VERSION 5.8 ;
BUSBITCHARS "[]" ;
DIVIDERCHAR "/" ;
UNITS
    DATABASE MICRONS 1000 ;
END UNITS

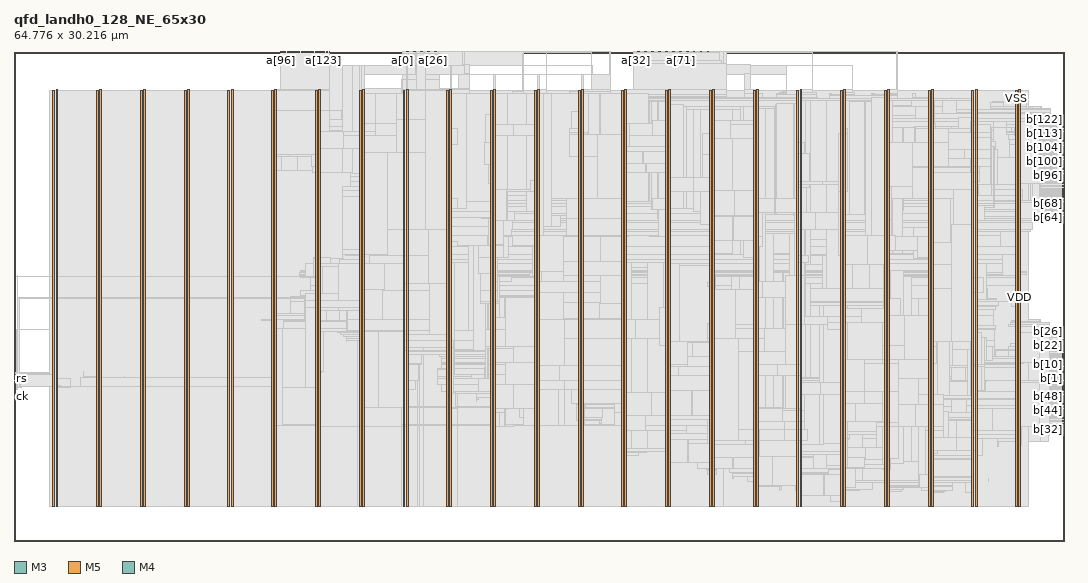
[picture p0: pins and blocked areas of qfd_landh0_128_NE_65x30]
MACRO qfd_landh0_128_NE_65x30
  FOREIGN qfd_landh0_128_NE_65x30 0 0 ;
  CLASS BLOCK ;
  SIZE 64.776 BY 30.216 ;
  PIN a[0]
    DIRECTION INPUT ;
    USE SIGNAL ;
    PORT
      LAYER M3 ;
        RECT  23.94 30.179 23.958 30.216 ;
    END
  END a[0]
  PIN a[100]
    DIRECTION INPUT ;
    USE SIGNAL ;
    PORT
      LAYER M5 ;
        RECT  16.848 30.132 16.872 30.216 ;
    END
  END a[100]
  PIN a[101]
    DIRECTION INPUT ;
    USE SIGNAL ;
    PORT
      LAYER M5 ;
        RECT  16.944 30.132 16.968 30.216 ;
    END
  END a[101]
  PIN a[102]
    DIRECTION INPUT ;
    USE SIGNAL ;
    PORT
      LAYER M5 ;
        RECT  17.04 30.132 17.064 30.216 ;
    END
  END a[102]
  PIN a[103]
    DIRECTION INPUT ;
    USE SIGNAL ;
    PORT
      LAYER M5 ;
        RECT  17.136 30.132 17.16 30.216 ;
    END
  END a[103]
  PIN a[104]
    DIRECTION INPUT ;
    USE SIGNAL ;
    PORT
      LAYER M5 ;
        RECT  17.232 30.132 17.256 30.216 ;
    END
  END a[104]
  PIN a[105]
    DIRECTION INPUT ;
    USE SIGNAL ;
    PORT
      LAYER M5 ;
        RECT  17.328 30.132 17.352 30.216 ;
    END
  END a[105]
  PIN a[106]
    DIRECTION INPUT ;
    USE SIGNAL ;
    PORT
      LAYER M5 ;
        RECT  17.424 30.132 17.448 30.216 ;
    END
  END a[106]
  PIN a[107]
    DIRECTION INPUT ;
    USE SIGNAL ;
    PORT
      LAYER M5 ;
        RECT  17.52 30.132 17.544 30.216 ;
    END
  END a[107]
  PIN a[108]
    DIRECTION INPUT ;
    USE SIGNAL ;
    PORT
      LAYER M5 ;
        RECT  17.616 30.132 17.64 30.216 ;
    END
  END a[108]
  PIN a[109]
    DIRECTION INPUT ;
    USE SIGNAL ;
    PORT
      LAYER M5 ;
        RECT  17.712 30.132 17.736 30.216 ;
    END
  END a[109]
  PIN a[10]
    DIRECTION INPUT ;
    USE SIGNAL ;
    PORT
      LAYER M3 ;
        RECT  24.66 30.179 24.678 30.216 ;
    END
  END a[10]
  PIN a[110]
    DIRECTION INPUT ;
    USE SIGNAL ;
    PORT
      LAYER M5 ;
        RECT  17.808 30.132 17.832 30.216 ;
    END
  END a[110]
  PIN a[111]
    DIRECTION INPUT ;
    USE SIGNAL ;
    PORT
      LAYER M5 ;
        RECT  17.904 30.132 17.928 30.216 ;
    END
  END a[111]
  PIN a[112]
    DIRECTION INPUT ;
    USE SIGNAL ;
    PORT
      LAYER M5 ;
        RECT  18 30.132 18.024 30.216 ;
    END
  END a[112]
  PIN a[113]
    DIRECTION INPUT ;
    USE SIGNAL ;
    PORT
      LAYER M5 ;
        RECT  18.096 30.132 18.12 30.216 ;
    END
  END a[113]
  PIN a[114]
    DIRECTION INPUT ;
    USE SIGNAL ;
    PORT
      LAYER M5 ;
        RECT  18.192 30.132 18.216 30.216 ;
    END
  END a[114]
  PIN a[115]
    DIRECTION INPUT ;
    USE SIGNAL ;
    PORT
      LAYER M5 ;
        RECT  18.288 30.132 18.312 30.216 ;
    END
  END a[115]
  PIN a[116]
    DIRECTION INPUT ;
    USE SIGNAL ;
    PORT
      LAYER M5 ;
        RECT  18.384 30.132 18.408 30.216 ;
    END
  END a[116]
  PIN a[117]
    DIRECTION INPUT ;
    USE SIGNAL ;
    PORT
      LAYER M5 ;
        RECT  18.48 30.132 18.504 30.216 ;
    END
  END a[117]
  PIN a[118]
    DIRECTION INPUT ;
    USE SIGNAL ;
    PORT
      LAYER M5 ;
        RECT  18.576 30.132 18.6 30.216 ;
    END
  END a[118]
  PIN a[119]
    DIRECTION INPUT ;
    USE SIGNAL ;
    PORT
      LAYER M5 ;
        RECT  18.672 30.132 18.696 30.216 ;
    END
  END a[119]
  PIN a[11]
    DIRECTION INPUT ;
    USE SIGNAL ;
    PORT
      LAYER M3 ;
        RECT  24.732 30.179 24.75 30.216 ;
    END
  END a[11]
  PIN a[120]
    DIRECTION INPUT ;
    USE SIGNAL ;
    PORT
      LAYER M5 ;
        RECT  18.768 30.132 18.792 30.216 ;
    END
  END a[120]
  PIN a[121]
    DIRECTION INPUT ;
    USE SIGNAL ;
    PORT
      LAYER M5 ;
        RECT  18.864 30.132 18.888 30.216 ;
    END
  END a[121]
  PIN a[122]
    DIRECTION INPUT ;
    USE SIGNAL ;
    PORT
      LAYER M5 ;
        RECT  18.96 30.132 18.984 30.216 ;
    END
  END a[122]
  PIN a[123]
    DIRECTION INPUT ;
    USE SIGNAL ;
    PORT
      LAYER M5 ;
        RECT  19.056 30.132 19.08 30.216 ;
    END
  END a[123]
  PIN a[124]
    DIRECTION INPUT ;
    USE SIGNAL ;
    PORT
      LAYER M5 ;
        RECT  19.152 30.132 19.176 30.216 ;
    END
  END a[124]
  PIN a[125]
    DIRECTION INPUT ;
    USE SIGNAL ;
    PORT
      LAYER M5 ;
        RECT  19.248 30.132 19.272 30.216 ;
    END
  END a[125]
  PIN a[126]
    DIRECTION INPUT ;
    USE SIGNAL ;
    PORT
      LAYER M5 ;
        RECT  19.344 30.132 19.368 30.216 ;
    END
  END a[126]
  PIN a[127]
    DIRECTION INPUT ;
    USE SIGNAL ;
    PORT
      LAYER M5 ;
        RECT  19.44 30.132 19.464 30.216 ;
    END
  END a[127]
  PIN a[12]
    DIRECTION INPUT ;
    USE SIGNAL ;
    PORT
      LAYER M3 ;
        RECT  24.804 30.179 24.822 30.216 ;
    END
  END a[12]
  PIN a[13]
    DIRECTION INPUT ;
    USE SIGNAL ;
    PORT
      LAYER M3 ;
        RECT  24.876 30.179 24.894 30.216 ;
    END
  END a[13]
  PIN a[14]
    DIRECTION INPUT ;
    USE SIGNAL ;
    PORT
      LAYER M3 ;
        RECT  24.948 30.179 24.966 30.216 ;
    END
  END a[14]
  PIN a[15]
    DIRECTION INPUT ;
    USE SIGNAL ;
    PORT
      LAYER M3 ;
        RECT  25.02 30.179 25.038 30.216 ;
    END
  END a[15]
  PIN a[16]
    DIRECTION INPUT ;
    USE SIGNAL ;
    PORT
      LAYER M3 ;
        RECT  25.092 30.179 25.11 30.216 ;
    END
  END a[16]
  PIN a[17]
    DIRECTION INPUT ;
    USE SIGNAL ;
    PORT
      LAYER M3 ;
        RECT  25.164 30.179 25.182 30.216 ;
    END
  END a[17]
  PIN a[18]
    DIRECTION INPUT ;
    USE SIGNAL ;
    PORT
      LAYER M3 ;
        RECT  25.236 30.179 25.254 30.216 ;
    END
  END a[18]
  PIN a[19]
    DIRECTION INPUT ;
    USE SIGNAL ;
    PORT
      LAYER M3 ;
        RECT  25.308 30.179 25.326 30.216 ;
    END
  END a[19]
  PIN a[1]
    DIRECTION INPUT ;
    USE SIGNAL ;
    PORT
      LAYER M3 ;
        RECT  24.012 30.179 24.03 30.216 ;
    END
  END a[1]
  PIN a[20]
    DIRECTION INPUT ;
    USE SIGNAL ;
    PORT
      LAYER M3 ;
        RECT  25.38 30.179 25.398 30.216 ;
    END
  END a[20]
  PIN a[21]
    DIRECTION INPUT ;
    USE SIGNAL ;
    PORT
      LAYER M3 ;
        RECT  25.452 30.179 25.47 30.216 ;
    END
  END a[21]
  PIN a[22]
    DIRECTION INPUT ;
    USE SIGNAL ;
    PORT
      LAYER M3 ;
        RECT  25.524 30.179 25.542 30.216 ;
    END
  END a[22]
  PIN a[23]
    DIRECTION INPUT ;
    USE SIGNAL ;
    PORT
      LAYER M3 ;
        RECT  25.596 30.179 25.614 30.216 ;
    END
  END a[23]
  PIN a[24]
    DIRECTION INPUT ;
    USE SIGNAL ;
    PORT
      LAYER M3 ;
        RECT  25.668 30.179 25.686 30.216 ;
    END
  END a[24]
  PIN a[25]
    DIRECTION INPUT ;
    USE SIGNAL ;
    PORT
      LAYER M3 ;
        RECT  25.74 30.179 25.758 30.216 ;
    END
  END a[25]
  PIN a[26]
    DIRECTION INPUT ;
    USE SIGNAL ;
    PORT
      LAYER M3 ;
        RECT  25.812 30.179 25.83 30.216 ;
    END
  END a[26]
  PIN a[27]
    DIRECTION INPUT ;
    USE SIGNAL ;
    PORT
      LAYER M3 ;
        RECT  25.884 30.179 25.902 30.216 ;
    END
  END a[27]
  PIN a[28]
    DIRECTION INPUT ;
    USE SIGNAL ;
    PORT
      LAYER M3 ;
        RECT  25.956 30.179 25.974 30.216 ;
    END
  END a[28]
  PIN a[29]
    DIRECTION INPUT ;
    USE SIGNAL ;
    PORT
      LAYER M3 ;
        RECT  26.028 30.179 26.046 30.216 ;
    END
  END a[29]
  PIN a[2]
    DIRECTION INPUT ;
    USE SIGNAL ;
    PORT
      LAYER M3 ;
        RECT  24.084 30.179 24.102 30.216 ;
    END
  END a[2]
  PIN a[30]
    DIRECTION INPUT ;
    USE SIGNAL ;
    PORT
      LAYER M3 ;
        RECT  26.1 30.179 26.118 30.216 ;
    END
  END a[30]
  PIN a[31]
    DIRECTION INPUT ;
    USE SIGNAL ;
    PORT
      LAYER M3 ;
        RECT  26.172 30.179 26.19 30.216 ;
    END
  END a[31]
  PIN a[32]
    DIRECTION INPUT ;
    USE SIGNAL ;
    PORT
      LAYER M3 ;
        RECT  38.34 30.179 38.358 30.216 ;
    END
  END a[32]
  PIN a[33]
    DIRECTION INPUT ;
    USE SIGNAL ;
    PORT
      LAYER M3 ;
        RECT  38.412 30.179 38.43 30.216 ;
    END
  END a[33]
  PIN a[34]
    DIRECTION INPUT ;
    USE SIGNAL ;
    PORT
      LAYER M3 ;
        RECT  38.484 30.179 38.502 30.216 ;
    END
  END a[34]
  PIN a[35]
    DIRECTION INPUT ;
    USE SIGNAL ;
    PORT
      LAYER M3 ;
        RECT  38.556 30.179 38.574 30.216 ;
    END
  END a[35]
  PIN a[36]
    DIRECTION INPUT ;
    USE SIGNAL ;
    PORT
      LAYER M3 ;
        RECT  38.628 30.179 38.646 30.216 ;
    END
  END a[36]
  PIN a[37]
    DIRECTION INPUT ;
    USE SIGNAL ;
    PORT
      LAYER M3 ;
        RECT  38.7 30.179 38.718 30.216 ;
    END
  END a[37]
  PIN a[38]
    DIRECTION INPUT ;
    USE SIGNAL ;
    PORT
      LAYER M3 ;
        RECT  38.772 30.179 38.79 30.216 ;
    END
  END a[38]
  PIN a[39]
    DIRECTION INPUT ;
    USE SIGNAL ;
    PORT
      LAYER M3 ;
        RECT  38.844 30.179 38.862 30.216 ;
    END
  END a[39]
  PIN a[3]
    DIRECTION INPUT ;
    USE SIGNAL ;
    PORT
      LAYER M3 ;
        RECT  24.156 30.179 24.174 30.216 ;
    END
  END a[3]
  PIN a[40]
    DIRECTION INPUT ;
    USE SIGNAL ;
    PORT
      LAYER M3 ;
        RECT  38.916 30.179 38.934 30.216 ;
    END
  END a[40]
  PIN a[41]
    DIRECTION INPUT ;
    USE SIGNAL ;
    PORT
      LAYER M3 ;
        RECT  38.988 30.179 39.006 30.216 ;
    END
  END a[41]
  PIN a[42]
    DIRECTION INPUT ;
    USE SIGNAL ;
    PORT
      LAYER M3 ;
        RECT  39.06 30.179 39.078 30.216 ;
    END
  END a[42]
  PIN a[43]
    DIRECTION INPUT ;
    USE SIGNAL ;
    PORT
      LAYER M3 ;
        RECT  39.132 30.179 39.15 30.216 ;
    END
  END a[43]
  PIN a[44]
    DIRECTION INPUT ;
    USE SIGNAL ;
    PORT
      LAYER M3 ;
        RECT  39.204 30.179 39.222 30.216 ;
    END
  END a[44]
  PIN a[45]
    DIRECTION INPUT ;
    USE SIGNAL ;
    PORT
      LAYER M3 ;
        RECT  39.276 30.179 39.294 30.216 ;
    END
  END a[45]
  PIN a[46]
    DIRECTION INPUT ;
    USE SIGNAL ;
    PORT
      LAYER M3 ;
        RECT  39.348 30.179 39.366 30.216 ;
    END
  END a[46]
  PIN a[47]
    DIRECTION INPUT ;
    USE SIGNAL ;
    PORT
      LAYER M3 ;
        RECT  39.42 30.179 39.438 30.216 ;
    END
  END a[47]
  PIN a[48]
    DIRECTION INPUT ;
    USE SIGNAL ;
    PORT
      LAYER M3 ;
        RECT  39.492 30.179 39.51 30.216 ;
    END
  END a[48]
  PIN a[49]
    DIRECTION INPUT ;
    USE SIGNAL ;
    PORT
      LAYER M3 ;
        RECT  39.564 30.179 39.582 30.216 ;
    END
  END a[49]
  PIN a[4]
    DIRECTION INPUT ;
    USE SIGNAL ;
    PORT
      LAYER M3 ;
        RECT  24.228 30.179 24.246 30.216 ;
    END
  END a[4]
  PIN a[50]
    DIRECTION INPUT ;
    USE SIGNAL ;
    PORT
      LAYER M3 ;
        RECT  39.636 30.179 39.654 30.216 ;
    END
  END a[50]
  PIN a[51]
    DIRECTION INPUT ;
    USE SIGNAL ;
    PORT
      LAYER M3 ;
        RECT  39.708 30.179 39.726 30.216 ;
    END
  END a[51]
  PIN a[52]
    DIRECTION INPUT ;
    USE SIGNAL ;
    PORT
      LAYER M3 ;
        RECT  39.78 30.179 39.798 30.216 ;
    END
  END a[52]
  PIN a[53]
    DIRECTION INPUT ;
    USE SIGNAL ;
    PORT
      LAYER M3 ;
        RECT  39.852 30.179 39.87 30.216 ;
    END
  END a[53]
  PIN a[54]
    DIRECTION INPUT ;
    USE SIGNAL ;
    PORT
      LAYER M3 ;
        RECT  39.924 30.179 39.942 30.216 ;
    END
  END a[54]
  PIN a[55]
    DIRECTION INPUT ;
    USE SIGNAL ;
    PORT
      LAYER M3 ;
        RECT  39.996 30.179 40.014 30.216 ;
    END
  END a[55]
  PIN a[56]
    DIRECTION INPUT ;
    USE SIGNAL ;
    PORT
      LAYER M3 ;
        RECT  40.068 30.179 40.086 30.216 ;
    END
  END a[56]
  PIN a[57]
    DIRECTION INPUT ;
    USE SIGNAL ;
    PORT
      LAYER M3 ;
        RECT  40.14 30.179 40.158 30.216 ;
    END
  END a[57]
  PIN a[58]
    DIRECTION INPUT ;
    USE SIGNAL ;
    PORT
      LAYER M3 ;
        RECT  40.212 30.179 40.23 30.216 ;
    END
  END a[58]
  PIN a[59]
    DIRECTION INPUT ;
    USE SIGNAL ;
    PORT
      LAYER M3 ;
        RECT  40.284 30.179 40.302 30.216 ;
    END
  END a[59]
  PIN a[5]
    DIRECTION INPUT ;
    USE SIGNAL ;
    PORT
      LAYER M3 ;
        RECT  24.3 30.179 24.318 30.216 ;
    END
  END a[5]
  PIN a[60]
    DIRECTION INPUT ;
    USE SIGNAL ;
    PORT
      LAYER M3 ;
        RECT  40.356 30.179 40.374 30.216 ;
    END
  END a[60]
  PIN a[61]
    DIRECTION INPUT ;
    USE SIGNAL ;
    PORT
      LAYER M3 ;
        RECT  40.428 30.179 40.446 30.216 ;
    END
  END a[61]
  PIN a[62]
    DIRECTION INPUT ;
    USE SIGNAL ;
    PORT
      LAYER M3 ;
        RECT  40.5 30.179 40.518 30.216 ;
    END
  END a[62]
  PIN a[63]
    DIRECTION INPUT ;
    USE SIGNAL ;
    PORT
      LAYER M3 ;
        RECT  40.572 30.179 40.59 30.216 ;
    END
  END a[63]
  PIN a[64]
    DIRECTION INPUT ;
    USE SIGNAL ;
    PORT
      LAYER M3 ;
        RECT  40.644 30.179 40.662 30.216 ;
    END
  END a[64]
  PIN a[65]
    DIRECTION INPUT ;
    USE SIGNAL ;
    PORT
      LAYER M3 ;
        RECT  40.716 30.179 40.734 30.216 ;
    END
  END a[65]
  PIN a[66]
    DIRECTION INPUT ;
    USE SIGNAL ;
    PORT
      LAYER M3 ;
        RECT  40.788 30.179 40.806 30.216 ;
    END
  END a[66]
  PIN a[67]
    DIRECTION INPUT ;
    USE SIGNAL ;
    PORT
      LAYER M3 ;
        RECT  40.86 30.179 40.878 30.216 ;
    END
  END a[67]
  PIN a[68]
    DIRECTION INPUT ;
    USE SIGNAL ;
    PORT
      LAYER M3 ;
        RECT  40.932 30.179 40.95 30.216 ;
    END
  END a[68]
  PIN a[69]
    DIRECTION INPUT ;
    USE SIGNAL ;
    PORT
      LAYER M3 ;
        RECT  41.004 30.179 41.022 30.216 ;
    END
  END a[69]
  PIN a[6]
    DIRECTION INPUT ;
    USE SIGNAL ;
    PORT
      LAYER M3 ;
        RECT  24.372 30.179 24.39 30.216 ;
    END
  END a[6]
  PIN a[70]
    DIRECTION INPUT ;
    USE SIGNAL ;
    PORT
      LAYER M3 ;
        RECT  41.076 30.179 41.094 30.216 ;
    END
  END a[70]
  PIN a[71]
    DIRECTION INPUT ;
    USE SIGNAL ;
    PORT
      LAYER M3 ;
        RECT  41.148 30.179 41.166 30.216 ;
    END
  END a[71]
  PIN a[72]
    DIRECTION INPUT ;
    USE SIGNAL ;
    PORT
      LAYER M3 ;
        RECT  41.22 30.179 41.238 30.216 ;
    END
  END a[72]
  PIN a[73]
    DIRECTION INPUT ;
    USE SIGNAL ;
    PORT
      LAYER M3 ;
        RECT  41.292 30.179 41.31 30.216 ;
    END
  END a[73]
  PIN a[74]
    DIRECTION INPUT ;
    USE SIGNAL ;
    PORT
      LAYER M3 ;
        RECT  41.364 30.179 41.382 30.216 ;
    END
  END a[74]
  PIN a[75]
    DIRECTION INPUT ;
    USE SIGNAL ;
    PORT
      LAYER M3 ;
        RECT  41.436 30.179 41.454 30.216 ;
    END
  END a[75]
  PIN a[76]
    DIRECTION INPUT ;
    USE SIGNAL ;
    PORT
      LAYER M3 ;
        RECT  41.508 30.179 41.526 30.216 ;
    END
  END a[76]
  PIN a[77]
    DIRECTION INPUT ;
    USE SIGNAL ;
    PORT
      LAYER M3 ;
        RECT  41.58 30.179 41.598 30.216 ;
    END
  END a[77]
  PIN a[78]
    DIRECTION INPUT ;
    USE SIGNAL ;
    PORT
      LAYER M3 ;
        RECT  41.652 30.179 41.67 30.216 ;
    END
  END a[78]
  PIN a[79]
    DIRECTION INPUT ;
    USE SIGNAL ;
    PORT
      LAYER M3 ;
        RECT  41.724 30.179 41.742 30.216 ;
    END
  END a[79]
  PIN a[7]
    DIRECTION INPUT ;
    USE SIGNAL ;
    PORT
      LAYER M3 ;
        RECT  24.444 30.179 24.462 30.216 ;
    END
  END a[7]
  PIN a[80]
    DIRECTION INPUT ;
    USE SIGNAL ;
    PORT
      LAYER M3 ;
        RECT  41.796 30.179 41.814 30.216 ;
    END
  END a[80]
  PIN a[81]
    DIRECTION INPUT ;
    USE SIGNAL ;
    PORT
      LAYER M3 ;
        RECT  41.868 30.179 41.886 30.216 ;
    END
  END a[81]
  PIN a[82]
    DIRECTION INPUT ;
    USE SIGNAL ;
    PORT
      LAYER M3 ;
        RECT  41.94 30.179 41.958 30.216 ;
    END
  END a[82]
  PIN a[83]
    DIRECTION INPUT ;
    USE SIGNAL ;
    PORT
      LAYER M3 ;
        RECT  42.012 30.179 42.03 30.216 ;
    END
  END a[83]
  PIN a[84]
    DIRECTION INPUT ;
    USE SIGNAL ;
    PORT
      LAYER M3 ;
        RECT  42.084 30.179 42.102 30.216 ;
    END
  END a[84]
  PIN a[85]
    DIRECTION INPUT ;
    USE SIGNAL ;
    PORT
      LAYER M3 ;
        RECT  42.156 30.179 42.174 30.216 ;
    END
  END a[85]
  PIN a[86]
    DIRECTION INPUT ;
    USE SIGNAL ;
    PORT
      LAYER M3 ;
        RECT  42.228 30.179 42.246 30.216 ;
    END
  END a[86]
  PIN a[87]
    DIRECTION INPUT ;
    USE SIGNAL ;
    PORT
      LAYER M3 ;
        RECT  42.3 30.179 42.318 30.216 ;
    END
  END a[87]
  PIN a[88]
    DIRECTION INPUT ;
    USE SIGNAL ;
    PORT
      LAYER M3 ;
        RECT  42.372 30.179 42.39 30.216 ;
    END
  END a[88]
  PIN a[89]
    DIRECTION INPUT ;
    USE SIGNAL ;
    PORT
      LAYER M3 ;
        RECT  42.444 30.179 42.462 30.216 ;
    END
  END a[89]
  PIN a[8]
    DIRECTION INPUT ;
    USE SIGNAL ;
    PORT
      LAYER M3 ;
        RECT  24.516 30.179 24.534 30.216 ;
    END
  END a[8]
  PIN a[90]
    DIRECTION INPUT ;
    USE SIGNAL ;
    PORT
      LAYER M3 ;
        RECT  42.516 30.179 42.534 30.216 ;
    END
  END a[90]
  PIN a[91]
    DIRECTION INPUT ;
    USE SIGNAL ;
    PORT
      LAYER M3 ;
        RECT  42.588 30.179 42.606 30.216 ;
    END
  END a[91]
  PIN a[92]
    DIRECTION INPUT ;
    USE SIGNAL ;
    PORT
      LAYER M3 ;
        RECT  42.66 30.179 42.678 30.216 ;
    END
  END a[92]
  PIN a[93]
    DIRECTION INPUT ;
    USE SIGNAL ;
    PORT
      LAYER M3 ;
        RECT  42.732 30.179 42.75 30.216 ;
    END
  END a[93]
  PIN a[94]
    DIRECTION INPUT ;
    USE SIGNAL ;
    PORT
      LAYER M3 ;
        RECT  42.804 30.179 42.822 30.216 ;
    END
  END a[94]
  PIN a[95]
    DIRECTION INPUT ;
    USE SIGNAL ;
    PORT
      LAYER M3 ;
        RECT  42.876 30.179 42.894 30.216 ;
    END
  END a[95]
  PIN a[96]
    DIRECTION INPUT ;
    USE SIGNAL ;
    PORT
      LAYER M5 ;
        RECT  16.464 30.132 16.488 30.216 ;
    END
  END a[96]
  PIN a[97]
    DIRECTION INPUT ;
    USE SIGNAL ;
    PORT
      LAYER M5 ;
        RECT  16.56 30.132 16.584 30.216 ;
    END
  END a[97]
  PIN a[98]
    DIRECTION INPUT ;
    USE SIGNAL ;
    PORT
      LAYER M5 ;
        RECT  16.656 30.132 16.68 30.216 ;
    END
  END a[98]
  PIN a[99]
    DIRECTION INPUT ;
    USE SIGNAL ;
    PORT
      LAYER M5 ;
        RECT  16.752 30.132 16.776 30.216 ;
    END
  END a[99]
  PIN a[9]
    DIRECTION INPUT ;
    USE SIGNAL ;
    PORT
      LAYER M3 ;
        RECT  24.588 30.179 24.606 30.216 ;
    END
  END a[9]
  PIN b[0]
    DIRECTION OUTPUT ;
    USE SIGNAL ;
    PORT
      LAYER M4 ;
        RECT  64.692 9.936 64.776 9.96 ;
    END
  END b[0]
  PIN b[100]
    DIRECTION OUTPUT ;
    USE SIGNAL ;
    PORT
      LAYER M4 ;
        RECT  64.692 23.376 64.776 23.4 ;
    END
  END b[100]
  PIN b[101]
    DIRECTION OUTPUT ;
    USE SIGNAL ;
    PORT
      LAYER M4 ;
        RECT  64.692 23.472 64.776 23.496 ;
    END
  END b[101]
  PIN b[102]
    DIRECTION OUTPUT ;
    USE SIGNAL ;
    PORT
      LAYER M4 ;
        RECT  64.692 23.568 64.776 23.592 ;
    END
  END b[102]
  PIN b[103]
    DIRECTION OUTPUT ;
    USE SIGNAL ;
    PORT
      LAYER M4 ;
        RECT  64.692 23.664 64.776 23.688 ;
    END
  END b[103]
  PIN b[104]
    DIRECTION OUTPUT ;
    USE SIGNAL ;
    PORT
      LAYER M4 ;
        RECT  64.692 23.76 64.776 23.784 ;
    END
  END b[104]
  PIN b[105]
    DIRECTION OUTPUT ;
    USE SIGNAL ;
    PORT
      LAYER M4 ;
        RECT  64.692 23.856 64.776 23.88 ;
    END
  END b[105]
  PIN b[106]
    DIRECTION OUTPUT ;
    USE SIGNAL ;
    PORT
      LAYER M4 ;
        RECT  64.692 23.952 64.776 23.976 ;
    END
  END b[106]
  PIN b[107]
    DIRECTION OUTPUT ;
    USE SIGNAL ;
    PORT
      LAYER M4 ;
        RECT  64.692 24.048 64.776 24.072 ;
    END
  END b[107]
  PIN b[108]
    DIRECTION OUTPUT ;
    USE SIGNAL ;
    PORT
      LAYER M4 ;
        RECT  64.692 24.144 64.776 24.168 ;
    END
  END b[108]
  PIN b[109]
    DIRECTION OUTPUT ;
    USE SIGNAL ;
    PORT
      LAYER M4 ;
        RECT  64.692 24.24 64.776 24.264 ;
    END
  END b[109]
  PIN b[10]
    DIRECTION OUTPUT ;
    USE SIGNAL ;
    PORT
      LAYER M4 ;
        RECT  64.692 10.896 64.776 10.92 ;
    END
  END b[10]
  PIN b[110]
    DIRECTION OUTPUT ;
    USE SIGNAL ;
    PORT
      LAYER M4 ;
        RECT  64.692 24.336 64.776 24.36 ;
    END
  END b[110]
  PIN b[111]
    DIRECTION OUTPUT ;
    USE SIGNAL ;
    PORT
      LAYER M4 ;
        RECT  64.692 24.432 64.776 24.456 ;
    END
  END b[111]
  PIN b[112]
    DIRECTION OUTPUT ;
    USE SIGNAL ;
    PORT
      LAYER M4 ;
        RECT  64.692 24.528 64.776 24.552 ;
    END
  END b[112]
  PIN b[113]
    DIRECTION OUTPUT ;
    USE SIGNAL ;
    PORT
      LAYER M4 ;
        RECT  64.692 24.624 64.776 24.648 ;
    END
  END b[113]
  PIN b[114]
    DIRECTION OUTPUT ;
    USE SIGNAL ;
    PORT
      LAYER M4 ;
        RECT  64.692 24.72 64.776 24.744 ;
    END
  END b[114]
  PIN b[115]
    DIRECTION OUTPUT ;
    USE SIGNAL ;
    PORT
      LAYER M4 ;
        RECT  64.692 24.816 64.776 24.84 ;
    END
  END b[115]
  PIN b[116]
    DIRECTION OUTPUT ;
    USE SIGNAL ;
    PORT
      LAYER M4 ;
        RECT  64.692 24.912 64.776 24.936 ;
    END
  END b[116]
  PIN b[117]
    DIRECTION OUTPUT ;
    USE SIGNAL ;
    PORT
      LAYER M4 ;
        RECT  64.692 25.008 64.776 25.032 ;
    END
  END b[117]
  PIN b[118]
    DIRECTION OUTPUT ;
    USE SIGNAL ;
    PORT
      LAYER M4 ;
        RECT  64.692 25.104 64.776 25.128 ;
    END
  END b[118]
  PIN b[119]
    DIRECTION OUTPUT ;
    USE SIGNAL ;
    PORT
      LAYER M4 ;
        RECT  64.692 25.2 64.776 25.224 ;
    END
  END b[119]
  PIN b[11]
    DIRECTION OUTPUT ;
    USE SIGNAL ;
    PORT
      LAYER M4 ;
        RECT  64.692 10.992 64.776 11.016 ;
    END
  END b[11]
  PIN b[120]
    DIRECTION OUTPUT ;
    USE SIGNAL ;
    PORT
      LAYER M4 ;
        RECT  64.692 25.296 64.776 25.32 ;
    END
  END b[120]
  PIN b[121]
    DIRECTION OUTPUT ;
    USE SIGNAL ;
    PORT
      LAYER M4 ;
        RECT  64.692 25.392 64.776 25.416 ;
    END
  END b[121]
  PIN b[122]
    DIRECTION OUTPUT ;
    USE SIGNAL ;
    PORT
      LAYER M4 ;
        RECT  64.692 25.488 64.776 25.512 ;
    END
  END b[122]
  PIN b[123]
    DIRECTION OUTPUT ;
    USE SIGNAL ;
    PORT
      LAYER M4 ;
        RECT  64.692 25.584 64.776 25.608 ;
    END
  END b[123]
  PIN b[124]
    DIRECTION OUTPUT ;
    USE SIGNAL ;
    PORT
      LAYER M4 ;
        RECT  64.692 25.68 64.776 25.704 ;
    END
  END b[124]
  PIN b[125]
    DIRECTION OUTPUT ;
    USE SIGNAL ;
    PORT
      LAYER M4 ;
        RECT  64.692 25.776 64.776 25.8 ;
    END
  END b[125]
  PIN b[126]
    DIRECTION OUTPUT ;
    USE SIGNAL ;
    PORT
      LAYER M4 ;
        RECT  64.692 25.872 64.776 25.896 ;
    END
  END b[126]
  PIN b[127]
    DIRECTION OUTPUT ;
    USE SIGNAL ;
    PORT
      LAYER M4 ;
        RECT  64.692 25.968 64.776 25.992 ;
    END
  END b[127]
  PIN b[12]
    DIRECTION OUTPUT ;
    USE SIGNAL ;
    PORT
      LAYER M4 ;
        RECT  64.692 11.088 64.776 11.112 ;
    END
  END b[12]
  PIN b[13]
    DIRECTION OUTPUT ;
    USE SIGNAL ;
    PORT
      LAYER M4 ;
        RECT  64.692 11.184 64.776 11.208 ;
    END
  END b[13]
  PIN b[14]
    DIRECTION OUTPUT ;
    USE SIGNAL ;
    PORT
      LAYER M4 ;
        RECT  64.692 11.28 64.776 11.304 ;
    END
  END b[14]
  PIN b[15]
    DIRECTION OUTPUT ;
    USE SIGNAL ;
    PORT
      LAYER M4 ;
        RECT  64.692 11.376 64.776 11.4 ;
    END
  END b[15]
  PIN b[16]
    DIRECTION OUTPUT ;
    USE SIGNAL ;
    PORT
      LAYER M4 ;
        RECT  64.692 11.472 64.776 11.496 ;
    END
  END b[16]
  PIN b[17]
    DIRECTION OUTPUT ;
    USE SIGNAL ;
    PORT
      LAYER M4 ;
        RECT  64.692 11.568 64.776 11.592 ;
    END
  END b[17]
  PIN b[18]
    DIRECTION OUTPUT ;
    USE SIGNAL ;
    PORT
      LAYER M4 ;
        RECT  64.692 11.664 64.776 11.688 ;
    END
  END b[18]
  PIN b[19]
    DIRECTION OUTPUT ;
    USE SIGNAL ;
    PORT
      LAYER M4 ;
        RECT  64.692 11.76 64.776 11.784 ;
    END
  END b[19]
  PIN b[1]
    DIRECTION OUTPUT ;
    USE SIGNAL ;
    PORT
      LAYER M4 ;
        RECT  64.692 10.032 64.776 10.056 ;
    END
  END b[1]
  PIN b[20]
    DIRECTION OUTPUT ;
    USE SIGNAL ;
    PORT
      LAYER M4 ;
        RECT  64.692 11.856 64.776 11.88 ;
    END
  END b[20]
  PIN b[21]
    DIRECTION OUTPUT ;
    USE SIGNAL ;
    PORT
      LAYER M4 ;
        RECT  64.692 11.952 64.776 11.976 ;
    END
  END b[21]
  PIN b[22]
    DIRECTION OUTPUT ;
    USE SIGNAL ;
    PORT
      LAYER M4 ;
        RECT  64.692 12.048 64.776 12.072 ;
    END
  END b[22]
  PIN b[23]
    DIRECTION OUTPUT ;
    USE SIGNAL ;
    PORT
      LAYER M4 ;
        RECT  64.692 12.144 64.776 12.168 ;
    END
  END b[23]
  PIN b[24]
    DIRECTION OUTPUT ;
    USE SIGNAL ;
    PORT
      LAYER M4 ;
        RECT  64.692 12.24 64.776 12.264 ;
    END
  END b[24]
  PIN b[25]
    DIRECTION OUTPUT ;
    USE SIGNAL ;
    PORT
      LAYER M4 ;
        RECT  64.692 12.336 64.776 12.36 ;
    END
  END b[25]
  PIN b[26]
    DIRECTION OUTPUT ;
    USE SIGNAL ;
    PORT
      LAYER M4 ;
        RECT  64.692 12.432 64.776 12.456 ;
    END
  END b[26]
  PIN b[27]
    DIRECTION OUTPUT ;
    USE SIGNAL ;
    PORT
      LAYER M4 ;
        RECT  64.692 12.528 64.776 12.552 ;
    END
  END b[27]
  PIN b[28]
    DIRECTION OUTPUT ;
    USE SIGNAL ;
    PORT
      LAYER M4 ;
        RECT  64.692 12.624 64.776 12.648 ;
    END
  END b[28]
  PIN b[29]
    DIRECTION OUTPUT ;
    USE SIGNAL ;
    PORT
      LAYER M4 ;
        RECT  64.692 12.72 64.776 12.744 ;
    END
  END b[29]
  PIN b[2]
    DIRECTION OUTPUT ;
    USE SIGNAL ;
    PORT
      LAYER M4 ;
        RECT  64.692 10.128 64.776 10.152 ;
    END
  END b[2]
  PIN b[30]
    DIRECTION OUTPUT ;
    USE SIGNAL ;
    PORT
      LAYER M4 ;
        RECT  64.692 12.816 64.776 12.84 ;
    END
  END b[30]
  PIN b[31]
    DIRECTION OUTPUT ;
    USE SIGNAL ;
    PORT
      LAYER M4 ;
        RECT  64.692 12.912 64.776 12.936 ;
    END
  END b[31]
  PIN b[32]
    DIRECTION OUTPUT ;
    USE SIGNAL ;
    PORT
      LAYER M4 ;
        RECT  64.692 6.864 64.776 6.888 ;
    END
  END b[32]
  PIN b[33]
    DIRECTION OUTPUT ;
    USE SIGNAL ;
    PORT
      LAYER M4 ;
        RECT  64.692 6.96 64.776 6.984 ;
    END
  END b[33]
  PIN b[34]
    DIRECTION OUTPUT ;
    USE SIGNAL ;
    PORT
      LAYER M4 ;
        RECT  64.692 7.056 64.776 7.08 ;
    END
  END b[34]
  PIN b[35]
    DIRECTION OUTPUT ;
    USE SIGNAL ;
    PORT
      LAYER M4 ;
        RECT  64.692 7.152 64.776 7.176 ;
    END
  END b[35]
  PIN b[36]
    DIRECTION OUTPUT ;
    USE SIGNAL ;
    PORT
      LAYER M4 ;
        RECT  64.692 7.248 64.776 7.272 ;
    END
  END b[36]
  PIN b[37]
    DIRECTION OUTPUT ;
    USE SIGNAL ;
    PORT
      LAYER M4 ;
        RECT  64.692 7.344 64.776 7.368 ;
    END
  END b[37]
  PIN b[38]
    DIRECTION OUTPUT ;
    USE SIGNAL ;
    PORT
      LAYER M4 ;
        RECT  64.692 7.44 64.776 7.464 ;
    END
  END b[38]
  PIN b[39]
    DIRECTION OUTPUT ;
    USE SIGNAL ;
    PORT
      LAYER M4 ;
        RECT  64.692 7.536 64.776 7.56 ;
    END
  END b[39]
  PIN b[3]
    DIRECTION OUTPUT ;
    USE SIGNAL ;
    PORT
      LAYER M4 ;
        RECT  64.692 10.224 64.776 10.248 ;
    END
  END b[3]
  PIN b[40]
    DIRECTION OUTPUT ;
    USE SIGNAL ;
    PORT
      LAYER M4 ;
        RECT  64.692 7.632 64.776 7.656 ;
    END
  END b[40]
  PIN b[41]
    DIRECTION OUTPUT ;
    USE SIGNAL ;
    PORT
      LAYER M4 ;
        RECT  64.692 7.728 64.776 7.752 ;
    END
  END b[41]
  PIN b[42]
    DIRECTION OUTPUT ;
    USE SIGNAL ;
    PORT
      LAYER M4 ;
        RECT  64.692 7.824 64.776 7.848 ;
    END
  END b[42]
  PIN b[43]
    DIRECTION OUTPUT ;
    USE SIGNAL ;
    PORT
      LAYER M4 ;
        RECT  64.692 7.92 64.776 7.944 ;
    END
  END b[43]
  PIN b[44]
    DIRECTION OUTPUT ;
    USE SIGNAL ;
    PORT
      LAYER M4 ;
        RECT  64.692 8.016 64.776 8.04 ;
    END
  END b[44]
  PIN b[45]
    DIRECTION OUTPUT ;
    USE SIGNAL ;
    PORT
      LAYER M4 ;
        RECT  64.692 8.112 64.776 8.136 ;
    END
  END b[45]
  PIN b[46]
    DIRECTION OUTPUT ;
    USE SIGNAL ;
    PORT
      LAYER M4 ;
        RECT  64.692 8.208 64.776 8.232 ;
    END
  END b[46]
  PIN b[47]
    DIRECTION OUTPUT ;
    USE SIGNAL ;
    PORT
      LAYER M4 ;
        RECT  64.692 8.304 64.776 8.328 ;
    END
  END b[47]
  PIN b[48]
    DIRECTION OUTPUT ;
    USE SIGNAL ;
    PORT
      LAYER M4 ;
        RECT  64.692 8.4 64.776 8.424 ;
    END
  END b[48]
  PIN b[49]
    DIRECTION OUTPUT ;
    USE SIGNAL ;
    PORT
      LAYER M4 ;
        RECT  64.692 8.496 64.776 8.52 ;
    END
  END b[49]
  PIN b[4]
    DIRECTION OUTPUT ;
    USE SIGNAL ;
    PORT
      LAYER M4 ;
        RECT  64.692 10.32 64.776 10.344 ;
    END
  END b[4]
  PIN b[50]
    DIRECTION OUTPUT ;
    USE SIGNAL ;
    PORT
      LAYER M4 ;
        RECT  64.692 8.592 64.776 8.616 ;
    END
  END b[50]
  PIN b[51]
    DIRECTION OUTPUT ;
    USE SIGNAL ;
    PORT
      LAYER M4 ;
        RECT  64.692 8.688 64.776 8.712 ;
    END
  END b[51]
  PIN b[52]
    DIRECTION OUTPUT ;
    USE SIGNAL ;
    PORT
      LAYER M4 ;
        RECT  64.692 8.784 64.776 8.808 ;
    END
  END b[52]
  PIN b[53]
    DIRECTION OUTPUT ;
    USE SIGNAL ;
    PORT
      LAYER M4 ;
        RECT  64.692 8.88 64.776 8.904 ;
    END
  END b[53]
  PIN b[54]
    DIRECTION OUTPUT ;
    USE SIGNAL ;
    PORT
      LAYER M4 ;
        RECT  64.692 8.976 64.776 9 ;
    END
  END b[54]
  PIN b[55]
    DIRECTION OUTPUT ;
    USE SIGNAL ;
    PORT
      LAYER M4 ;
        RECT  64.692 9.072 64.776 9.096 ;
    END
  END b[55]
  PIN b[56]
    DIRECTION OUTPUT ;
    USE SIGNAL ;
    PORT
      LAYER M4 ;
        RECT  64.692 9.168 64.776 9.192 ;
    END
  END b[56]
  PIN b[57]
    DIRECTION OUTPUT ;
    USE SIGNAL ;
    PORT
      LAYER M4 ;
        RECT  64.692 9.264 64.776 9.288 ;
    END
  END b[57]
  PIN b[58]
    DIRECTION OUTPUT ;
    USE SIGNAL ;
    PORT
      LAYER M4 ;
        RECT  64.692 9.36 64.776 9.384 ;
    END
  END b[58]
  PIN b[59]
    DIRECTION OUTPUT ;
    USE SIGNAL ;
    PORT
      LAYER M4 ;
        RECT  64.692 9.456 64.776 9.48 ;
    END
  END b[59]
  PIN b[5]
    DIRECTION OUTPUT ;
    USE SIGNAL ;
    PORT
      LAYER M4 ;
        RECT  64.692 10.416 64.776 10.44 ;
    END
  END b[5]
  PIN b[60]
    DIRECTION OUTPUT ;
    USE SIGNAL ;
    PORT
      LAYER M4 ;
        RECT  64.692 9.552 64.776 9.576 ;
    END
  END b[60]
  PIN b[61]
    DIRECTION OUTPUT ;
    USE SIGNAL ;
    PORT
      LAYER M4 ;
        RECT  64.692 9.648 64.776 9.672 ;
    END
  END b[61]
  PIN b[62]
    DIRECTION OUTPUT ;
    USE SIGNAL ;
    PORT
      LAYER M4 ;
        RECT  64.692 9.744 64.776 9.768 ;
    END
  END b[62]
  PIN b[63]
    DIRECTION OUTPUT ;
    USE SIGNAL ;
    PORT
      LAYER M4 ;
        RECT  64.692 9.84 64.776 9.864 ;
    END
  END b[63]
  PIN b[64]
    DIRECTION OUTPUT ;
    USE SIGNAL ;
    PORT
      LAYER M4 ;
        RECT  64.692 19.92 64.776 19.944 ;
    END
  END b[64]
  PIN b[65]
    DIRECTION OUTPUT ;
    USE SIGNAL ;
    PORT
      LAYER M4 ;
        RECT  64.692 20.016 64.776 20.04 ;
    END
  END b[65]
  PIN b[66]
    DIRECTION OUTPUT ;
    USE SIGNAL ;
    PORT
      LAYER M4 ;
        RECT  64.692 20.112 64.776 20.136 ;
    END
  END b[66]
  PIN b[67]
    DIRECTION OUTPUT ;
    USE SIGNAL ;
    PORT
      LAYER M4 ;
        RECT  64.692 20.208 64.776 20.232 ;
    END
  END b[67]
  PIN b[68]
    DIRECTION OUTPUT ;
    USE SIGNAL ;
    PORT
      LAYER M4 ;
        RECT  64.692 20.304 64.776 20.328 ;
    END
  END b[68]
  PIN b[69]
    DIRECTION OUTPUT ;
    USE SIGNAL ;
    PORT
      LAYER M4 ;
        RECT  64.692 20.4 64.776 20.424 ;
    END
  END b[69]
  PIN b[6]
    DIRECTION OUTPUT ;
    USE SIGNAL ;
    PORT
      LAYER M4 ;
        RECT  64.692 10.512 64.776 10.536 ;
    END
  END b[6]
  PIN b[70]
    DIRECTION OUTPUT ;
    USE SIGNAL ;
    PORT
      LAYER M4 ;
        RECT  64.692 20.496 64.776 20.52 ;
    END
  END b[70]
  PIN b[71]
    DIRECTION OUTPUT ;
    USE SIGNAL ;
    PORT
      LAYER M4 ;
        RECT  64.692 20.592 64.776 20.616 ;
    END
  END b[71]
  PIN b[72]
    DIRECTION OUTPUT ;
    USE SIGNAL ;
    PORT
      LAYER M4 ;
        RECT  64.692 20.688 64.776 20.712 ;
    END
  END b[72]
  PIN b[73]
    DIRECTION OUTPUT ;
    USE SIGNAL ;
    PORT
      LAYER M4 ;
        RECT  64.692 20.784 64.776 20.808 ;
    END
  END b[73]
  PIN b[74]
    DIRECTION OUTPUT ;
    USE SIGNAL ;
    PORT
      LAYER M4 ;
        RECT  64.692 20.88 64.776 20.904 ;
    END
  END b[74]
  PIN b[75]
    DIRECTION OUTPUT ;
    USE SIGNAL ;
    PORT
      LAYER M4 ;
        RECT  64.692 20.976 64.776 21 ;
    END
  END b[75]
  PIN b[76]
    DIRECTION OUTPUT ;
    USE SIGNAL ;
    PORT
      LAYER M4 ;
        RECT  64.692 21.072 64.776 21.096 ;
    END
  END b[76]
  PIN b[77]
    DIRECTION OUTPUT ;
    USE SIGNAL ;
    PORT
      LAYER M4 ;
        RECT  64.692 21.168 64.776 21.192 ;
    END
  END b[77]
  PIN b[78]
    DIRECTION OUTPUT ;
    USE SIGNAL ;
    PORT
      LAYER M4 ;
        RECT  64.692 21.264 64.776 21.288 ;
    END
  END b[78]
  PIN b[79]
    DIRECTION OUTPUT ;
    USE SIGNAL ;
    PORT
      LAYER M4 ;
        RECT  64.692 21.36 64.776 21.384 ;
    END
  END b[79]
  PIN b[7]
    DIRECTION OUTPUT ;
    USE SIGNAL ;
    PORT
      LAYER M4 ;
        RECT  64.692 10.608 64.776 10.632 ;
    END
  END b[7]
  PIN b[80]
    DIRECTION OUTPUT ;
    USE SIGNAL ;
    PORT
      LAYER M4 ;
        RECT  64.692 21.456 64.776 21.48 ;
    END
  END b[80]
  PIN b[81]
    DIRECTION OUTPUT ;
    USE SIGNAL ;
    PORT
      LAYER M4 ;
        RECT  64.692 21.552 64.776 21.576 ;
    END
  END b[81]
  PIN b[82]
    DIRECTION OUTPUT ;
    USE SIGNAL ;
    PORT
      LAYER M4 ;
        RECT  64.692 21.648 64.776 21.672 ;
    END
  END b[82]
  PIN b[83]
    DIRECTION OUTPUT ;
    USE SIGNAL ;
    PORT
      LAYER M4 ;
        RECT  64.692 21.744 64.776 21.768 ;
    END
  END b[83]
  PIN b[84]
    DIRECTION OUTPUT ;
    USE SIGNAL ;
    PORT
      LAYER M4 ;
        RECT  64.692 21.84 64.776 21.864 ;
    END
  END b[84]
  PIN b[85]
    DIRECTION OUTPUT ;
    USE SIGNAL ;
    PORT
      LAYER M4 ;
        RECT  64.692 21.936 64.776 21.96 ;
    END
  END b[85]
  PIN b[86]
    DIRECTION OUTPUT ;
    USE SIGNAL ;
    PORT
      LAYER M4 ;
        RECT  64.692 22.032 64.776 22.056 ;
    END
  END b[86]
  PIN b[87]
    DIRECTION OUTPUT ;
    USE SIGNAL ;
    PORT
      LAYER M4 ;
        RECT  64.692 22.128 64.776 22.152 ;
    END
  END b[87]
  PIN b[88]
    DIRECTION OUTPUT ;
    USE SIGNAL ;
    PORT
      LAYER M4 ;
        RECT  64.692 22.224 64.776 22.248 ;
    END
  END b[88]
  PIN b[89]
    DIRECTION OUTPUT ;
    USE SIGNAL ;
    PORT
      LAYER M4 ;
        RECT  64.692 22.32 64.776 22.344 ;
    END
  END b[89]
  PIN b[8]
    DIRECTION OUTPUT ;
    USE SIGNAL ;
    PORT
      LAYER M4 ;
        RECT  64.692 10.704 64.776 10.728 ;
    END
  END b[8]
  PIN b[90]
    DIRECTION OUTPUT ;
    USE SIGNAL ;
    PORT
      LAYER M4 ;
        RECT  64.692 22.416 64.776 22.44 ;
    END
  END b[90]
  PIN b[91]
    DIRECTION OUTPUT ;
    USE SIGNAL ;
    PORT
      LAYER M4 ;
        RECT  64.692 22.512 64.776 22.536 ;
    END
  END b[91]
  PIN b[92]
    DIRECTION OUTPUT ;
    USE SIGNAL ;
    PORT
      LAYER M4 ;
        RECT  64.692 22.608 64.776 22.632 ;
    END
  END b[92]
  PIN b[93]
    DIRECTION OUTPUT ;
    USE SIGNAL ;
    PORT
      LAYER M4 ;
        RECT  64.692 22.704 64.776 22.728 ;
    END
  END b[93]
  PIN b[94]
    DIRECTION OUTPUT ;
    USE SIGNAL ;
    PORT
      LAYER M4 ;
        RECT  64.692 22.8 64.776 22.824 ;
    END
  END b[94]
  PIN b[95]
    DIRECTION OUTPUT ;
    USE SIGNAL ;
    PORT
      LAYER M4 ;
        RECT  64.692 22.896 64.776 22.92 ;
    END
  END b[95]
  PIN b[96]
    DIRECTION OUTPUT ;
    USE SIGNAL ;
    PORT
      LAYER M4 ;
        RECT  64.692 22.992 64.776 23.016 ;
    END
  END b[96]
  PIN b[97]
    DIRECTION OUTPUT ;
    USE SIGNAL ;
    PORT
      LAYER M4 ;
        RECT  64.692 23.088 64.776 23.112 ;
    END
  END b[97]
  PIN b[98]
    DIRECTION OUTPUT ;
    USE SIGNAL ;
    PORT
      LAYER M4 ;
        RECT  64.692 23.184 64.776 23.208 ;
    END
  END b[98]
  PIN b[99]
    DIRECTION OUTPUT ;
    USE SIGNAL ;
    PORT
      LAYER M4 ;
        RECT  64.692 23.28 64.776 23.304 ;
    END
  END b[99]
  PIN b[9]
    DIRECTION OUTPUT ;
    USE SIGNAL ;
    PORT
      LAYER M4 ;
        RECT  64.692 10.8 64.776 10.824 ;
    END
  END b[9]
  PIN ck
    DIRECTION INPUT ;
    USE SIGNAL ;
    PORT
      LAYER M4 ;
        RECT  0 9.36 0.084 9.384 ;
    END
  END ck
  PIN ck_s
    DIRECTION INPUT ;
    USE SIGNAL ;
    PORT
      LAYER M4 ;
        RECT  0 9.456 0.084 9.48 ;
    END
  END ck_s
  PIN en
    DIRECTION INPUT ;
    USE SIGNAL ;
    PORT
      LAYER M4 ;
        RECT  0 9.552 0.084 9.576 ;
    END
  END en
  PIN fault
    DIRECTION OUTPUT ;
    USE SIGNAL ;
    PORT
      LAYER M4 ;
        RECT  0 9.648 0.084 9.672 ;
    END
  END fault
  PIN k0
    DIRECTION INPUT ;
    USE SIGNAL ;
    PORT
      LAYER M4 ;
        RECT  0 9.744 0.084 9.768 ;
    END
  END k0
  PIN k1
    DIRECTION INPUT ;
    USE SIGNAL ;
    PORT
      LAYER M4 ;
        RECT  0 9.84 0.084 9.864 ;
    END
  END k1
  PIN k2
    DIRECTION INPUT ;
    USE SIGNAL ;
    PORT
      LAYER M4 ;
        RECT  0 9.936 0.084 9.96 ;
    END
  END k2
  PIN rs
    DIRECTION INPUT ;
    USE SIGNAL ;
    PORT
      LAYER M4 ;
        RECT  0 10.032 0.084 10.056 ;
    END
  END rs
  PIN tie_hi
    DIRECTION OUTPUT ;
    USE SIGNAL ;
    PORT
      LAYER M4 ;
        RECT  0 10.128 0.084 10.152 ;
    END
  END tie_hi
  PIN tie_lo
    DIRECTION OUTPUT ;
    USE SIGNAL ;
    PORT
      LAYER M4 ;
        RECT  0 10.224 0.084 10.248 ;
    END
  END tie_lo
  PIN VDD
    DIRECTION INOUT ;
    USE POWER ;
    PORT
      LAYER M5 ;
        RECT  61.992 2.151 62.112 27.833 ;
        RECT  59.292 2.151 59.412 27.833 ;
        RECT  56.592 2.151 56.712 27.833 ;
        RECT  53.892 2.151 54.012 27.833 ;
        RECT  51.192 2.151 51.312 27.833 ;
        RECT  48.492 2.151 48.612 27.833 ;
        RECT  45.792 2.151 45.912 27.833 ;
        RECT  43.092 2.151 43.212 27.833 ;
        RECT  40.392 2.151 40.512 27.833 ;
        RECT  37.692 2.151 37.812 27.833 ;
        RECT  34.992 2.151 35.112 27.833 ;
        RECT  32.292 2.151 32.412 27.833 ;
        RECT  29.592 2.151 29.712 27.833 ;
        RECT  26.892 2.151 27.012 27.833 ;
        RECT  24.192 2.151 24.312 27.833 ;
        RECT  21.492 2.151 21.612 27.833 ;
        RECT  18.792 2.151 18.912 27.833 ;
        RECT  16.092 2.151 16.212 27.833 ;
        RECT  13.392 2.151 13.512 27.833 ;
        RECT  10.692 2.151 10.812 27.833 ;
        RECT  7.992 2.151 8.112 27.833 ;
        RECT  5.292 2.151 5.412 27.833 ;
        RECT  2.592 2.151 2.712 27.833 ;
    END
  END VDD
  PIN VSS
    DIRECTION INOUT ;
    USE GROUND ;
    PORT
      LAYER M5 ;
        RECT  61.8 2.137 61.92 27.819 ;
        RECT  59.1 2.137 59.22 27.819 ;
        RECT  56.4 2.137 56.52 27.819 ;
        RECT  53.7 2.137 53.82 27.819 ;
        RECT  51 2.137 51.12 27.819 ;
        RECT  48.3 2.137 48.42 27.819 ;
        RECT  45.6 2.137 45.72 27.819 ;
        RECT  42.9 2.137 43.02 27.819 ;
        RECT  40.2 2.137 40.32 27.819 ;
        RECT  37.5 2.137 37.62 27.819 ;
        RECT  34.8 2.137 34.92 27.819 ;
        RECT  32.1 2.137 32.22 27.819 ;
        RECT  29.4 2.137 29.52 27.819 ;
        RECT  26.7 2.137 26.82 27.819 ;
        RECT  24 2.137 24.12 27.819 ;
        RECT  21.3 2.137 21.42 27.819 ;
        RECT  18.6 2.137 18.72 27.819 ;
        RECT  15.9 2.137 16.02 27.819 ;
        RECT  13.2 2.137 13.32 27.819 ;
        RECT  10.5 2.137 10.62 27.819 ;
        RECT  7.8 2.137 7.92 27.819 ;
        RECT  5.1 2.137 5.22 27.819 ;
        RECT  2.4 2.137 2.52 27.819 ;
    END
  END VSS
  # OT_OBS_CLOSED layer=M5 d_um=1.536 added=149
  OBS
    LAYER RVTN ;
     RECT  2.16 2.16 62.586 2.295 ;
     RECT  2.16 2.565 62.586 2.835 ;
     RECT  2.16 3.105 62.586 3.375 ;
     RECT  2.16 3.645 62.586 3.915 ;
     RECT  2.16 4.185 62.586 4.455 ;
     RECT  2.16 4.725 62.586 4.995 ;
     RECT  2.16 5.265 62.586 5.535 ;
     RECT  2.16 5.805 62.586 6.075 ;
     RECT  2.16 6.345 62.586 6.615 ;
     RECT  2.16 6.885 62.586 7.155 ;
     RECT  2.16 7.425 62.586 7.695 ;
     RECT  2.16 7.965 62.586 8.235 ;
     RECT  2.16 8.505 62.586 8.775 ;
     RECT  2.16 9.045 62.586 9.315 ;
     RECT  2.16 9.585 62.586 9.855 ;
     RECT  2.16 10.125 62.586 10.395 ;
     RECT  2.16 10.665 62.586 10.935 ;
     RECT  2.16 11.205 62.586 11.475 ;
     RECT  2.16 11.745 62.586 12.015 ;
     RECT  2.16 12.285 62.586 12.555 ;
     RECT  2.16 12.825 62.586 13.095 ;
     RECT  2.16 13.365 62.586 13.635 ;
     RECT  2.16 13.905 62.586 14.175 ;
     RECT  2.16 14.445 62.586 14.715 ;
     RECT  2.16 14.985 62.586 15.255 ;
     RECT  2.16 15.525 62.586 15.795 ;
     RECT  2.16 16.065 62.586 16.335 ;
     RECT  2.16 16.605 62.586 16.875 ;
     RECT  2.16 17.145 62.586 17.415 ;
     RECT  2.16 17.685 62.586 17.955 ;
     RECT  2.16 18.225 62.586 18.495 ;
     RECT  2.16 18.765 62.586 19.035 ;
     RECT  2.16 19.305 62.586 19.575 ;
     RECT  2.16 19.845 62.586 20.115 ;
     RECT  2.16 20.385 62.586 20.655 ;
     RECT  2.16 20.925 62.586 21.195 ;
     RECT  2.16 21.465 62.586 21.735 ;
     RECT  2.16 22.005 62.586 22.275 ;
     RECT  2.16 22.545 62.586 22.815 ;
     RECT  2.16 23.085 62.586 23.355 ;
     RECT  2.16 23.625 62.586 23.895 ;
     RECT  2.16 24.165 62.586 24.435 ;
     RECT  2.16 24.705 62.586 24.975 ;
     RECT  2.16 25.245 62.586 25.515 ;
     RECT  2.16 25.785 62.586 26.055 ;
     RECT  2.16 26.325 62.586 26.595 ;
     RECT  2.16 26.865 62.586 27.135 ;
     RECT  2.16 27.405 62.586 27.675 ;
    LAYER RVTP ;
     RECT  2.16 2.295 62.586 2.565 ;
     RECT  2.16 2.835 62.586 3.105 ;
     RECT  2.16 3.375 62.586 3.645 ;
     RECT  2.16 3.915 62.586 4.185 ;
     RECT  2.16 4.455 62.586 4.725 ;
     RECT  2.16 4.995 62.586 5.265 ;
     RECT  2.16 5.535 62.586 5.805 ;
     RECT  2.16 6.075 62.586 6.345 ;
     RECT  2.16 6.615 62.586 6.885 ;
     RECT  2.16 7.155 62.586 7.425 ;
     RECT  2.16 7.695 62.586 7.965 ;
     RECT  2.16 8.235 62.586 8.505 ;
     RECT  2.16 8.775 62.586 9.045 ;
     RECT  2.16 9.315 62.586 9.585 ;
     RECT  2.16 9.855 62.586 10.125 ;
     RECT  2.16 10.395 62.586 10.665 ;
     RECT  2.16 10.935 62.586 11.205 ;
     RECT  2.16 11.475 62.586 11.745 ;
     RECT  2.16 12.015 62.586 12.285 ;
     RECT  2.16 12.555 62.586 12.825 ;
     RECT  2.16 13.095 62.586 13.365 ;
     RECT  2.16 13.635 62.586 13.905 ;
     RECT  2.16 14.175 62.586 14.445 ;
     RECT  2.16 14.715 62.586 14.985 ;
     RECT  2.16 15.255 62.586 15.525 ;
     RECT  2.16 15.795 62.586 16.065 ;
     RECT  2.16 16.335 62.586 16.605 ;
     RECT  2.16 16.875 62.586 17.145 ;
     RECT  2.16 17.415 62.586 17.685 ;
     RECT  2.16 17.955 62.586 18.225 ;
     RECT  2.16 18.495 62.586 18.765 ;
     RECT  2.16 19.035 62.586 19.305 ;
     RECT  2.16 19.575 62.586 19.845 ;
     RECT  2.16 20.115 62.586 20.385 ;
     RECT  2.16 20.655 62.586 20.925 ;
     RECT  2.16 21.195 62.586 21.465 ;
     RECT  2.16 21.735 62.586 22.005 ;
     RECT  2.16 22.275 62.586 22.545 ;
     RECT  2.16 22.815 62.586 23.085 ;
     RECT  2.16 23.355 62.586 23.625 ;
     RECT  2.16 23.895 62.586 24.165 ;
     RECT  2.16 24.435 62.586 24.705 ;
     RECT  2.16 24.975 62.586 25.245 ;
     RECT  2.16 25.515 62.586 25.785 ;
     RECT  2.16 26.055 62.586 26.325 ;
     RECT  2.16 26.595 62.586 26.865 ;
     RECT  2.16 27.135 62.586 27.405 ;
     RECT  2.16 27.675 62.586 27.81 ;
    LAYER M1 ;
     RECT  2.16 2.151 62.586 27.819 ;
    LAYER M2 ;
     RECT  0.103 10.368 0.139 10.386 ;
     RECT  0.139 10.332 2.16 10.386 ;
     RECT  0.175 13.032 2.16 13.05 ;
     RECT  2.16 2.151 21.163 27.819 ;
     RECT  21.163 2.151 23.935 27.936 ;
     RECT  24.007 29.376 24.223 29.394 ;
     RECT  23.971 30.15 24.223 30.168 ;
     RECT  23.935 2.151 24.907 28.476 ;
     RECT  24.223 29.376 24.907 30.168 ;
     RECT  24.907 2.151 25.007 30.168 ;
     RECT  25.007 29.34 25.195 30.168 ;
     RECT  25.007 2.151 25.259 28.404 ;
     RECT  25.259 2.151 27.347 27.936 ;
     RECT  25.195 29.34 31.415 30.204 ;
     RECT  31.415 30.114 32.855 30.204 ;
     RECT  32.855 30.15 35.627 30.204 ;
     RECT  31.415 29.34 35.663 29.358 ;
     RECT  35.627 30.186 36.779 30.204 ;
     RECT  38.227 30.15 38.839 30.168 ;
     RECT  38.839 30.114 38.911 30.168 ;
     RECT  38.911 29.916 39.091 30.168 ;
     RECT  39.091 29.844 39.163 30.168 ;
     RECT  39.163 29.691 39.343 30.168 ;
     RECT  39.343 29.421 39.379 30.168 ;
     RECT  39.379 29.421 39.919 30.204 ;
     RECT  39.919 29.376 40.135 30.204 ;
     RECT  27.347 2.151 40.279 27.819 ;
     RECT  40.135 28.764 40.279 30.204 ;
     RECT  40.279 2.151 43.763 30.204 ;
     RECT  43.763 28.764 43.979 30.204 ;
     RECT  43.979 28.764 45.455 29.394 ;
     RECT  45.455 28.764 47.651 29.358 ;
     RECT  43.979 30.15 49.271 30.204 ;
     RECT  47.651 29.34 51.755 29.358 ;
     RECT  49.271 30.186 54.491 30.204 ;
     RECT  43.763 2.151 62.586 27.819 ;
     RECT  62.586 19.116 62.735 26.784 ;
     RECT  62.735 19.206 62.807 26.784 ;
     RECT  62.586 6.156 63.311 13.662 ;
     RECT  62.807 19.656 63.311 26.784 ;
     RECT  63.311 8.748 63.347 13.464 ;
     RECT  63.311 19.926 63.347 24.534 ;
     RECT  63.347 8.748 63.383 12.654 ;
     RECT  63.347 20.016 63.383 21.654 ;
     RECT  63.347 22.482 63.383 24.264 ;
     RECT  63.311 25.686 63.383 26.784 ;
     RECT  63.311 6.156 63.815 7.884 ;
     RECT  63.815 6.516 63.887 7.884 ;
     RECT  63.383 8.748 63.887 9.612 ;
     RECT  63.383 10.44 63.887 12.654 ;
     RECT  63.347 13.446 63.887 13.464 ;
     RECT  63.383 20.358 63.887 21.654 ;
     RECT  63.383 23.292 63.887 24.264 ;
     RECT  63.383 26.37 63.887 26.658 ;
     RECT  63.887 8.748 63.923 8.766 ;
     RECT  63.887 11.376 63.923 11.394 ;
     RECT  63.887 20.43 63.923 20.448 ;
     RECT  63.887 21.474 63.923 21.654 ;
     RECT  63.887 26.406 63.923 26.658 ;
     RECT  63.887 7.128 63.959 7.524 ;
     RECT  63.923 21.474 63.959 21.492 ;
     RECT  63.923 26.406 63.959 26.424 ;
     RECT  63.959 7.128 63.995 7.146 ;
     RECT  64.651 22.131 64.751 22.149 ;
    LAYER M3 ;
     RECT  2.415 2.143 2.505 2.413 ;
     RECT  5.115 2.143 5.205 2.413 ;
     RECT  7.815 2.143 7.905 2.413 ;
     RECT  10.515 2.143 10.605 2.413 ;
     RECT  13.215 2.143 13.305 2.413 ;
     RECT  15.915 2.143 16.005 2.413 ;
     RECT  18.615 2.143 18.705 2.413 ;
     RECT  21.315 2.143 21.405 2.413 ;
     RECT  24.015 2.143 24.105 2.413 ;
     RECT  26.715 2.143 26.805 2.413 ;
     RECT  29.415 2.143 29.505 2.413 ;
     RECT  32.115 2.143 32.205 2.413 ;
     RECT  34.815 2.143 34.905 2.413 ;
     RECT  37.515 2.143 37.605 2.413 ;
     RECT  40.215 2.143 40.305 2.413 ;
     RECT  42.915 2.143 43.005 2.413 ;
     RECT  45.615 2.143 45.705 2.413 ;
     RECT  48.315 2.143 48.405 2.413 ;
     RECT  51.015 2.143 51.105 2.413 ;
     RECT  53.715 2.143 53.805 2.413 ;
     RECT  56.415 2.143 56.505 2.413 ;
     RECT  59.115 2.143 59.205 2.413 ;
     RECT  61.815 2.143 61.905 2.413 ;
     RECT  51.015 2.413 51.297 2.461 ;
     RECT  50.4 2.461 51.297 2.803 ;
     RECT  49.752 2.803 51.297 2.861 ;
     RECT  56.415 2.413 56.697 3.001 ;
     RECT  59.115 2.413 59.397 3.001 ;
     RECT  53.715 2.413 53.997 3.037 ;
     RECT  56.415 3.001 57.33 3.073 ;
     RECT  56.415 3.073 57.438 3.109 ;
     RECT  48.315 2.413 48.597 3.145 ;
     RECT  49.932 2.861 51.297 3.145 ;
     RECT  52.164 3.109 52.182 3.145 ;
     RECT  56.415 3.109 57.906 3.145 ;
     RECT  47.196 3.145 47.214 3.181 ;
     RECT  49.932 3.145 52.182 3.181 ;
     RECT  53.715 3.037 54.774 3.181 ;
     RECT  45.615 2.413 45.897 3.343 ;
     RECT  47.196 3.181 47.358 3.343 ;
     RECT  55.98 3.145 57.906 3.379 ;
     RECT  53.715 3.181 54.882 3.451 ;
     RECT  55.8 3.379 57.906 3.451 ;
     RECT  49.932 3.181 52.974 3.613 ;
     RECT  53.715 3.451 57.906 3.613 ;
     RECT  58.68 3.001 59.397 3.613 ;
     RECT  45.615 3.343 47.358 3.685 ;
     RECT  49.932 3.613 59.397 3.713 ;
     RECT  48.24 3.145 48.597 3.721 ;
     RECT  49.932 3.713 51.534 3.721 ;
     RECT  60.12 3.685 60.138 3.839 ;
     RECT  48.24 3.721 51.534 3.931 ;
     RECT  44.352 3.883 44.37 3.955 ;
     RECT  45.252 3.685 47.358 3.955 ;
     RECT  42.915 2.413 43.197 4.117 ;
     RECT  44.352 3.955 47.358 4.153 ;
     RECT  48.204 3.931 51.534 4.153 ;
     RECT  44.352 4.153 51.534 4.225 ;
     RECT  42.768 4.117 43.326 4.351 ;
     RECT  42.768 4.351 43.362 4.387 ;
     RECT  44.136 4.225 51.534 4.487 ;
     RECT  42.732 4.387 43.362 4.495 ;
     RECT  50.148 4.487 51.534 4.649 ;
     RECT  40.215 2.413 40.497 4.891 ;
     RECT  41.364 4.843 41.382 4.891 ;
     RECT  52.344 3.713 59.397 5.035 ;
     RECT  40.215 4.891 41.382 5.071 ;
     RECT  42.156 4.495 43.362 5.071 ;
     RECT  52.272 5.035 59.397 5.099 ;
     RECT  44.136 4.487 49.302 5.161 ;
     RECT  40.215 5.071 43.362 5.197 ;
     RECT  44.1 5.161 49.302 5.197 ;
     RECT  52.344 5.099 59.397 5.269 ;
     RECT  37.515 2.413 37.797 5.305 ;
     RECT  40.215 5.197 49.302 5.341 ;
     RECT  50.148 4.649 51.297 5.341 ;
     RECT  37.515 5.305 38.538 5.431 ;
     RECT  37.515 5.431 39.042 5.503 ;
     RECT  40.176 5.341 51.297 5.503 ;
     RECT  61.815 2.413 62.097 5.881 ;
     RECT  60.696 5.845 60.714 6.115 ;
     RECT  61.815 5.881 62.154 6.115 ;
     RECT  37.515 5.503 51.297 6.277 ;
     RECT  37.515 6.277 51.462 6.313 ;
     RECT  52.344 5.269 59.742 6.349 ;
     RECT  60.696 6.115 62.154 6.349 ;
     RECT  63.792 6.151 63.81 6.511 ;
     RECT  37.515 6.313 51.534 6.547 ;
     RECT  52.344 6.349 62.154 6.547 ;
     RECT  63.792 6.511 63.882 6.691 ;
     RECT  63.288 6.691 63.882 6.781 ;
     RECT  21.315 2.413 21.597 7.051 ;
     RECT  26.715 2.413 26.997 7.051 ;
     RECT  21.204 7.051 21.597 7.088 ;
     RECT  32.115 2.413 32.397 7.123 ;
     RECT  63.252 6.781 63.882 7.123 ;
     RECT  26.676 7.051 26.997 7.181 ;
     RECT  30.78 7.051 30.798 7.181 ;
     RECT  36.144 7.195 36.162 7.231 ;
     RECT  29.415 2.413 29.697 7.393 ;
     RECT  31.932 7.123 32.397 7.393 ;
     RECT  34.815 2.413 35.097 7.429 ;
     RECT  36.144 7.231 36.234 7.429 ;
     RECT  31.86 7.393 32.397 7.465 ;
     RECT  33.3 7.429 33.318 7.465 ;
     RECT  31.86 7.465 33.318 7.501 ;
     RECT  34.704 7.429 36.234 7.501 ;
     RECT  37.515 6.547 62.154 7.501 ;
     RECT  63.252 7.123 63.99 7.501 ;
     RECT  37.515 7.501 63.99 7.591 ;
     RECT  37.044 7.591 63.99 7.619 ;
     RECT  31.608 7.501 36.234 7.627 ;
     RECT  47.412 7.619 63.99 7.925 ;
     RECT  29.415 7.393 30.294 8.041 ;
     RECT  29.415 8.041 30.33 8.131 ;
     RECT  29.415 8.131 30.402 8.155 ;
     RECT  31.212 7.627 36.306 8.155 ;
     RECT  26.715 7.181 26.997 8.167 ;
     RECT  29.415 8.155 36.306 8.167 ;
     RECT  37.044 7.619 46.674 8.167 ;
     RECT  47.412 7.925 57.834 8.285 ;
     RECT  58.752 7.925 63.99 8.333 ;
     RECT  29.415 8.167 46.674 8.536 ;
     RECT  28.512 8.581 28.53 8.707 ;
     RECT  47.484 8.285 57.834 8.707 ;
     RECT  58.752 8.333 63.918 8.707 ;
     RECT  47.484 8.707 63.918 8.771 ;
     RECT  28.512 8.707 28.638 8.851 ;
     RECT  29.415 8.536 46.71 8.851 ;
     RECT  28.512 8.851 46.71 9.085 ;
     RECT  26.715 8.167 27.342 9.121 ;
     RECT  28.224 9.085 46.71 9.121 ;
     RECT  26.715 9.121 46.71 9.211 ;
     RECT  47.484 8.771 63.882 9.211 ;
     RECT  26.715 9.211 63.882 9.239 ;
     RECT  26.715 9.239 28.674 9.247 ;
     RECT  24.015 2.413 24.297 9.355 ;
     RECT  2.415 2.413 2.697 9.499 ;
     RECT  3.492 9.481 3.51 9.499 ;
     RECT  26.352 9.247 28.674 9.625 ;
     RECT  0.432 9.499 0.45 9.677 ;
     RECT  5.115 2.413 5.397 9.859 ;
     RECT  29.415 9.239 63.882 9.887 ;
     RECT  24.015 9.355 24.786 9.895 ;
     RECT  29.415 9.887 62.097 9.923 ;
     RECT  4.68 9.859 5.397 9.931 ;
     RECT  22.392 9.751 22.41 10.021 ;
     RECT  26.136 9.625 28.674 10.021 ;
     RECT  29.415 9.923 57.834 10.021 ;
     RECT  2.415 9.499 3.51 10.027 ;
     RECT  2.304 10.027 3.51 10.049 ;
     RECT  4.68 9.931 5.454 10.049 ;
     RECT  2.304 10.049 2.697 10.057 ;
     RECT  4.68 10.049 5.397 10.057 ;
     RECT  15.915 2.413 16.197 10.093 ;
     RECT  4.14 10.057 5.397 10.109 ;
     RECT  4.284 10.109 5.397 10.121 ;
     RECT  6.804 9.859 6.822 10.121 ;
     RECT  26.136 10.021 57.834 10.121 ;
     RECT  2.268 10.057 2.697 10.253 ;
     RECT  18.615 2.413 18.897 10.363 ;
     RECT  0.108 9.739 0.198 10.391 ;
     RECT  18.504 10.363 18.897 10.399 ;
     RECT  4.284 10.121 4.302 10.427 ;
     RECT  18.504 10.399 18.954 10.435 ;
     RECT  22.392 10.021 22.446 10.435 ;
     RECT  26.136 10.121 36.27 10.637 ;
     RECT  37.116 10.121 57.834 10.705 ;
     RECT  58.716 9.923 62.097 10.705 ;
     RECT  24.015 9.895 24.93 10.867 ;
     RECT  26.388 10.637 36.27 10.867 ;
     RECT  37.116 10.705 62.097 10.867 ;
     RECT  24.015 10.867 25.11 10.975 ;
     RECT  26.388 10.867 62.097 10.975 ;
     RECT  26.388 10.975 62.262 10.987 ;
     RECT  63.288 9.887 63.882 10.987 ;
     RECT  26.388 10.987 63.882 11.275 ;
     RECT  26.388 11.275 63.918 11.399 ;
     RECT  26.388 11.399 60.534 11.407 ;
     RECT  23.508 10.975 25.11 11.479 ;
     RECT  26.244 11.407 60.534 11.479 ;
     RECT  23.508 11.479 60.534 11.705 ;
     RECT  61.344 11.399 63.882 11.975 ;
     RECT  61.452 11.975 63.882 12.209 ;
     RECT  21.315 7.088 21.597 12.217 ;
     RECT  21.315 12.217 21.654 12.253 ;
     RECT  22.392 10.435 22.77 12.253 ;
     RECT  20.52 12.325 20.538 12.361 ;
     RECT  21.315 12.253 22.77 12.361 ;
     RECT  23.508 11.705 60.498 12.389 ;
     RECT  20.52 12.361 22.77 12.523 ;
     RECT  23.508 12.389 25.758 12.523 ;
     RECT  20.52 12.523 25.758 12.631 ;
     RECT  20.304 12.631 25.758 12.755 ;
     RECT  20.304 12.755 25.47 12.757 ;
     RECT  20.124 12.757 25.47 12.865 ;
     RECT  15.915 10.093 16.29 12.901 ;
     RECT  18.504 10.435 19.098 12.901 ;
     RECT  19.944 12.865 25.47 12.901 ;
     RECT  26.496 12.389 60.498 13.027 ;
     RECT  0.18 10.391 0.198 13.055 ;
     RECT  26.496 13.027 60.57 13.091 ;
     RECT  15.915 12.901 16.722 13.099 ;
     RECT  17.82 12.901 25.47 13.099 ;
     RECT  61.815 12.209 63.882 13.261 ;
     RECT  26.715 13.091 60.57 13.289 ;
     RECT  61.344 13.261 63.882 13.361 ;
     RECT  61.488 13.361 63.882 13.469 ;
     RECT  15.915 13.099 25.47 13.531 ;
     RECT  61.524 13.469 63.306 13.559 ;
     RECT  61.524 13.559 62.097 13.595 ;
     RECT  15.876 13.531 25.47 13.627 ;
     RECT  15.3 13.627 25.47 13.667 ;
     RECT  63.288 13.559 63.306 13.667 ;
     RECT  26.715 13.289 60.426 13.901 ;
     RECT  15.876 13.667 25.47 13.937 ;
     RECT  15.876 13.937 19.242 14.009 ;
     RECT  58.752 13.901 60.426 14.251 ;
     RECT  20.124 13.937 25.47 14.377 ;
     RECT  26.715 13.901 57.942 14.377 ;
     RECT  20.124 14.377 57.942 14.429 ;
     RECT  58.752 14.251 60.57 14.485 ;
     RECT  61.815 13.595 62.097 14.485 ;
     RECT  58.752 14.485 60.642 14.521 ;
     RECT  47.052 14.429 57.942 14.711 ;
     RECT  58.752 14.521 60.75 14.755 ;
     RECT  61.524 14.485 62.097 14.755 ;
     RECT  47.268 14.711 57.942 14.783 ;
     RECT  17.064 14.009 19.242 14.791 ;
     RECT  20.124 14.429 46.278 14.791 ;
     RECT  47.304 14.783 57.942 14.791 ;
     RECT  58.752 14.755 62.097 14.791 ;
     RECT  17.064 14.791 46.278 15.053 ;
     RECT  17.676 15.053 46.278 15.151 ;
     RECT  17.676 15.151 46.386 15.449 ;
     RECT  18.288 15.449 46.386 15.739 ;
     RECT  47.304 14.791 62.097 15.739 ;
     RECT  18.288 15.739 62.097 16.231 ;
     RECT  17.676 16.231 62.097 16.375 ;
     RECT  17.64 16.375 62.097 16.411 ;
     RECT  17.64 16.411 62.442 16.565 ;
     RECT  17.676 16.565 62.442 16.637 ;
     RECT  17.676 16.637 62.097 16.709 ;
     RECT  18 16.709 62.097 17.117 ;
     RECT  18.468 17.117 62.097 17.339 ;
     RECT  18.468 17.339 19.278 17.483 ;
     RECT  20.268 17.339 62.097 17.651 ;
     RECT  20.268 17.651 21.69 17.987 ;
     RECT  22.572 17.651 62.097 18.185 ;
     RECT  22.572 18.185 60.858 18.833 ;
     RECT  30.708 18.833 60.858 19.075 ;
     RECT  61.815 18.185 62.097 19.075 ;
     RECT  30.708 19.075 62.097 19.111 ;
     RECT  30.708 19.111 62.73 19.201 ;
     RECT  30.708 19.201 62.802 19.229 ;
     RECT  22.572 18.833 29.934 19.373 ;
     RECT  30.78 19.229 62.802 19.651 ;
     RECT  30.78 19.651 63.306 19.769 ;
     RECT  57.816 19.769 63.306 19.921 ;
     RECT  22.572 19.373 29.826 19.949 ;
     RECT  57.816 19.921 63.342 20.011 ;
     RECT  30.78 19.769 56.97 20.191 ;
     RECT  22.572 19.949 29.697 20.345 ;
     RECT  57.816 20.011 63.378 20.353 ;
     RECT  57.816 20.353 63.882 20.425 ;
     RECT  30.42 20.191 56.97 20.615 ;
     RECT  30.456 20.615 56.97 20.821 ;
     RECT  57.816 20.425 63.918 20.821 ;
     RECT  30.456 20.821 63.918 20.993 ;
     RECT  22.752 20.345 29.697 21.127 ;
     RECT  20.268 17.987 21.654 21.235 ;
     RECT  22.716 21.127 29.697 21.235 ;
     RECT  30.456 20.993 62.19 21.299 ;
     RECT  63.288 20.993 63.918 21.469 ;
     RECT  20.268 21.235 29.697 21.643 ;
     RECT  30.456 21.299 59.526 21.643 ;
     RECT  60.3 21.299 62.19 21.659 ;
     RECT  20.268 21.643 59.526 21.839 ;
     RECT  63.288 21.469 63.954 21.965 ;
     RECT  60.3 21.659 62.097 22.061 ;
     RECT  64.728 22.075 64.746 22.12 ;
     RECT  64.656 22.12 64.746 22.154 ;
     RECT  64.656 22.154 64.674 22.157 ;
     RECT  61.308 22.061 62.097 22.199 ;
     RECT  20.772 21.839 59.526 22.207 ;
     RECT  60.3 22.061 60.462 22.207 ;
     RECT  61.452 22.199 62.097 22.411 ;
     RECT  63.288 21.965 63.378 22.411 ;
     RECT  20.772 22.207 60.462 22.469 ;
     RECT  61.452 22.411 63.378 22.469 ;
     RECT  20.772 22.469 60.354 22.747 ;
     RECT  18.615 17.483 18.897 22.891 ;
     RECT  18.615 22.891 18.954 23.009 ;
     RECT  18.615 23.009 18.897 23.089 ;
     RECT  18.216 23.089 18.897 23.125 ;
     RECT  61.56 22.469 63.378 23.287 ;
     RECT  20.592 22.747 60.354 23.323 ;
     RECT  20.592 23.323 60.822 23.371 ;
     RECT  20.196 23.371 60.822 23.557 ;
     RECT  61.56 23.287 63.882 23.557 ;
     RECT  20.196 23.557 63.882 23.645 ;
     RECT  20.196 23.645 60.642 23.899 ;
     RECT  17.604 23.125 18.897 24.089 ;
     RECT  19.728 23.899 60.642 24.173 ;
     RECT  17.424 24.205 17.442 24.269 ;
     RECT  61.416 23.645 63.882 24.461 ;
     RECT  19.728 24.173 60.57 24.629 ;
     RECT  18.216 24.089 18.897 24.781 ;
     RECT  19.728 24.629 60.426 24.781 ;
     RECT  61.416 24.461 63.378 24.781 ;
     RECT  61.344 24.781 63.378 25.051 ;
     RECT  61.2 25.051 63.378 25.195 ;
     RECT  61.2 25.195 63.882 25.291 ;
     RECT  18.216 24.781 60.426 25.313 ;
     RECT  18.216 25.313 28.314 25.555 ;
     RECT  61.2 25.291 63.918 25.675 ;
     RECT  29.088 25.313 60.426 25.861 ;
     RECT  61.2 25.675 63.954 25.861 ;
     RECT  18.18 25.555 28.314 25.979 ;
     RECT  29.088 25.861 63.954 26.087 ;
     RECT  20.196 25.979 28.314 26.221 ;
     RECT  29.088 26.087 55.638 26.221 ;
     RECT  56.415 26.087 63.954 26.393 ;
     RECT  58.14 26.393 63.954 26.429 ;
     RECT  58.14 26.429 63.918 26.591 ;
     RECT  60.264 26.591 63.918 26.663 ;
     RECT  60.264 26.663 63.378 26.699 ;
     RECT  63.36 26.699 63.378 26.789 ;
     RECT  18.18 25.979 19.386 26.797 ;
     RECT  20.196 26.221 55.638 26.797 ;
     RECT  60.264 26.699 62.442 26.825 ;
     RECT  18.18 26.797 55.638 26.833 ;
     RECT  56.415 26.393 57.258 26.833 ;
     RECT  60.264 26.825 61.038 27.059 ;
     RECT  60.336 27.059 61.038 27.095 ;
     RECT  17.064 25.285 17.082 27.103 ;
     RECT  18.18 26.833 57.258 27.163 ;
     RECT  58.14 26.591 59.397 27.163 ;
     RECT  61.776 26.825 62.442 27.167 ;
     RECT  18.18 27.163 59.397 27.203 ;
     RECT  23.688 27.203 33.318 27.239 ;
     RECT  61.776 27.167 62.097 27.239 ;
     RECT  18.18 27.203 22.842 27.329 ;
     RECT  34.056 27.203 59.397 27.329 ;
     RECT  17.064 27.103 17.298 27.337 ;
     RECT  18.18 27.329 21.762 27.365 ;
     RECT  23.688 27.239 33.282 27.365 ;
     RECT  34.056 27.329 49.554 27.365 ;
     RECT  55.44 27.329 56.697 27.365 ;
     RECT  57.816 27.329 57.834 27.365 ;
     RECT  18.18 27.365 21.597 27.389 ;
     RECT  34.2 27.365 43.974 27.401 ;
     RECT  22.536 27.329 22.842 27.437 ;
     RECT  28.836 27.365 33.282 27.473 ;
     RECT  50.292 27.329 54.486 27.473 ;
     RECT  17.028 27.337 17.298 27.481 ;
     RECT  18.18 27.389 20.034 27.481 ;
     RECT  29.376 27.473 33.282 27.509 ;
     RECT  2.415 10.253 2.697 27.557 ;
     RECT  5.115 10.121 5.397 27.557 ;
     RECT  7.815 2.413 8.097 27.557 ;
     RECT  10.515 2.413 10.797 27.557 ;
     RECT  13.215 2.413 13.497 27.557 ;
     RECT  15.915 14.009 16.197 27.557 ;
     RECT  29.415 27.509 29.697 27.557 ;
     RECT  37.515 27.401 43.974 27.557 ;
     RECT  47.052 27.365 49.518 27.557 ;
     RECT  50.292 27.473 51.858 27.557 ;
     RECT  52.92 27.473 54.486 27.557 ;
     RECT  56.415 27.365 56.697 27.557 ;
     RECT  59.115 27.329 59.397 27.557 ;
     RECT  61.815 27.239 62.097 27.557 ;
     RECT  22.536 27.437 22.626 27.599 ;
     RECT  30.78 27.509 33.174 27.599 ;
     RECT  45.072 27.365 46.17 27.599 ;
     RECT  47.052 27.557 47.646 27.599 ;
     RECT  50.292 27.557 50.454 27.599 ;
     RECT  52.92 27.557 53.082 27.599 ;
     RECT  53.856 27.557 54.486 27.599 ;
     RECT  55.44 27.365 55.638 27.599 ;
     RECT  22.536 27.599 22.554 27.635 ;
     RECT  30.78 27.599 31.482 27.635 ;
     RECT  32.307 27.599 33.174 27.635 ;
     RECT  34.2 27.401 36.774 27.635 ;
     RECT  45.072 27.599 46.062 27.635 ;
     RECT  50.292 27.599 50.31 27.635 ;
     RECT  55.44 27.599 55.458 27.635 ;
     RECT  47.232 27.599 47.646 27.671 ;
     RECT  48.507 27.557 49.518 27.671 ;
     RECT  51.207 27.557 51.858 27.671 ;
     RECT  30.78 27.635 31.41 27.743 ;
     RECT  34.272 27.635 36.774 27.743 ;
     RECT  47.412 27.671 47.646 27.743 ;
     RECT  2.607 27.557 2.697 27.827 ;
     RECT  5.307 27.557 5.397 27.827 ;
     RECT  8.007 27.557 8.097 27.827 ;
     RECT  10.707 27.557 10.797 27.827 ;
     RECT  13.407 27.557 13.497 27.827 ;
     RECT  16.107 27.557 16.197 27.827 ;
     RECT  21.024 27.389 21.597 27.827 ;
     RECT  23.976 27.365 28.098 27.827 ;
     RECT  29.607 27.557 29.697 27.827 ;
     RECT  32.307 27.635 32.85 27.827 ;
     RECT  35.007 27.743 36.774 27.827 ;
     RECT  37.707 27.557 43.974 27.827 ;
     RECT  45.072 27.635 45.897 27.827 ;
     RECT  48.507 27.671 49.266 27.827 ;
     RECT  51.207 27.671 51.75 27.827 ;
     RECT  53.907 27.599 54.486 27.827 ;
     RECT  56.607 27.557 56.697 27.827 ;
     RECT  59.307 27.557 59.397 27.827 ;
     RECT  62.007 27.557 62.097 27.827 ;
     RECT  21.024 27.827 21.186 27.941 ;
     RECT  27.324 27.827 28.098 27.941 ;
     RECT  17.028 27.481 20.034 27.965 ;
     RECT  17.028 27.965 19.926 28.013 ;
     RECT  18.18 28.013 19.386 28.061 ;
     RECT  21.024 27.941 21.042 28.061 ;
     RECT  18.72 28.061 19.386 28.157 ;
     RECT  19.332 28.157 19.35 28.253 ;
     RECT  17.028 28.013 17.082 28.397 ;
     RECT  23.976 27.827 26.226 28.453 ;
     RECT  17.064 28.397 17.082 28.493 ;
     RECT  35.604 27.827 36.774 28.781 ;
     RECT  47.628 27.743 47.646 28.787 ;
     RECT  45.072 27.827 45.45 28.823 ;
     RECT  27.396 27.941 28.098 28.829 ;
     RECT  35.604 28.781 35.658 29.363 ;
     RECT  51.732 27.827 51.75 29.363 ;
     RECT  27.648 28.829 28.098 29.399 ;
     RECT  45.432 28.823 45.45 29.399 ;
     RECT  38.232 27.827 43.974 29.444 ;
     RECT  38.232 29.444 43.65 29.633 ;
     RECT  23.94 28.453 26.226 30.001 ;
     RECT  23.94 30.001 26.298 30.101 ;
     RECT  31.392 27.743 31.41 30.101 ;
     RECT  19.116 29.947 19.134 30.125 ;
     RECT  32.832 27.827 32.85 30.137 ;
     RECT  38.232 29.633 43.506 30.137 ;
     RECT  27.648 29.399 27.774 30.173 ;
     RECT  35.604 29.363 35.622 30.173 ;
     RECT  38.232 30.137 42.894 30.173 ;
     RECT  49.248 27.827 49.266 30.173 ;
     RECT  23.94 30.101 26.19 30.179 ;
     RECT  23.958 30.179 24.012 30.204 ;
     RECT  24.03 30.179 24.084 30.204 ;
     RECT  24.102 30.179 24.156 30.204 ;
     RECT  24.174 30.179 24.228 30.204 ;
     RECT  24.246 30.179 24.3 30.204 ;
     RECT  24.318 30.179 24.372 30.204 ;
     RECT  24.39 30.179 24.444 30.204 ;
     RECT  24.462 30.179 24.516 30.204 ;
     RECT  24.534 30.179 24.588 30.204 ;
     RECT  24.606 30.179 24.66 30.204 ;
     RECT  24.678 30.179 24.732 30.204 ;
     RECT  24.75 30.179 24.804 30.204 ;
     RECT  24.822 30.179 24.876 30.204 ;
     RECT  24.894 30.179 24.948 30.204 ;
     RECT  24.966 30.179 25.02 30.204 ;
     RECT  25.038 30.179 25.092 30.204 ;
     RECT  25.11 30.179 25.164 30.204 ;
     RECT  25.182 30.179 25.236 30.204 ;
     RECT  25.254 30.179 25.308 30.204 ;
     RECT  25.326 30.179 25.38 30.204 ;
     RECT  25.398 30.179 25.452 30.204 ;
     RECT  25.47 30.179 25.524 30.204 ;
     RECT  25.542 30.179 25.596 30.204 ;
     RECT  25.614 30.179 25.668 30.204 ;
     RECT  25.686 30.179 25.74 30.204 ;
     RECT  25.758 30.179 25.812 30.204 ;
     RECT  25.83 30.179 25.884 30.204 ;
     RECT  25.902 30.179 25.956 30.204 ;
     RECT  25.974 30.179 26.028 30.204 ;
     RECT  26.046 30.179 26.1 30.204 ;
     RECT  26.118 30.179 26.172 30.204 ;
     RECT  38.34 30.173 42.894 30.179 ;
     RECT  38.358 30.179 38.412 30.204 ;
     RECT  38.43 30.179 38.484 30.204 ;
     RECT  38.502 30.179 38.556 30.204 ;
     RECT  38.574 30.179 38.628 30.204 ;
     RECT  38.646 30.179 38.7 30.204 ;
     RECT  38.718 30.179 38.772 30.204 ;
     RECT  38.79 30.179 38.844 30.204 ;
     RECT  38.862 30.179 38.916 30.204 ;
     RECT  38.934 30.179 38.988 30.204 ;
     RECT  39.006 30.179 39.06 30.204 ;
     RECT  39.078 30.179 39.132 30.204 ;
     RECT  39.15 30.179 39.204 30.204 ;
     RECT  39.222 30.179 39.276 30.204 ;
     RECT  39.294 30.179 39.348 30.204 ;
     RECT  39.366 30.179 39.42 30.204 ;
     RECT  39.438 30.179 39.492 30.204 ;
     RECT  39.51 30.179 39.564 30.204 ;
     RECT  39.582 30.179 39.636 30.204 ;
     RECT  39.654 30.179 39.708 30.204 ;
     RECT  39.726 30.179 39.78 30.204 ;
     RECT  39.798 30.179 39.852 30.204 ;
     RECT  39.87 30.179 39.924 30.204 ;
     RECT  39.942 30.179 39.996 30.204 ;
     RECT  40.014 30.179 40.068 30.204 ;
     RECT  40.086 30.179 40.14 30.204 ;
     RECT  40.158 30.179 40.212 30.204 ;
     RECT  40.23 30.179 40.284 30.204 ;
     RECT  40.302 30.179 40.356 30.204 ;
     RECT  40.374 30.179 40.428 30.204 ;
     RECT  40.446 30.179 40.5 30.204 ;
     RECT  40.518 30.179 40.572 30.204 ;
     RECT  40.59 30.179 40.644 30.204 ;
     RECT  40.662 30.179 40.716 30.204 ;
     RECT  40.734 30.179 40.788 30.204 ;
     RECT  40.806 30.179 40.86 30.204 ;
     RECT  40.878 30.179 40.932 30.204 ;
     RECT  40.95 30.179 41.004 30.204 ;
     RECT  41.022 30.179 41.076 30.204 ;
     RECT  41.094 30.179 41.148 30.204 ;
     RECT  41.166 30.179 41.22 30.204 ;
     RECT  41.238 30.179 41.292 30.204 ;
     RECT  41.31 30.179 41.364 30.204 ;
     RECT  41.382 30.179 41.436 30.204 ;
     RECT  41.454 30.179 41.508 30.204 ;
     RECT  41.526 30.179 41.58 30.204 ;
     RECT  41.598 30.179 41.652 30.204 ;
     RECT  41.67 30.179 41.724 30.204 ;
     RECT  41.742 30.179 41.796 30.204 ;
     RECT  41.814 30.179 41.868 30.204 ;
     RECT  41.886 30.179 41.94 30.204 ;
     RECT  41.958 30.179 42.012 30.204 ;
     RECT  42.03 30.179 42.084 30.204 ;
     RECT  42.102 30.179 42.156 30.204 ;
     RECT  42.174 30.179 42.228 30.204 ;
     RECT  42.246 30.179 42.3 30.204 ;
     RECT  42.318 30.179 42.372 30.204 ;
     RECT  42.39 30.179 42.444 30.204 ;
     RECT  42.462 30.179 42.516 30.204 ;
     RECT  42.534 30.179 42.588 30.204 ;
     RECT  42.606 30.179 42.66 30.204 ;
     RECT  42.678 30.179 42.732 30.204 ;
     RECT  42.75 30.179 42.804 30.204 ;
     RECT  42.822 30.179 42.876 30.204 ;
     RECT  25.2 30.204 25.218 30.209 ;
     RECT  36.756 28.781 36.774 30.209 ;
     RECT  39.384 30.204 39.402 30.209 ;
     RECT  54.468 27.827 54.486 30.209 ;
    LAYER M4 ;
     RECT  0.084 9.36 0.227 9.384 ;
     RECT  0.06 9.384 0.227 9.456 ;
     RECT  0.084 9.456 0.227 9.48 ;
     RECT  0.06 9.48 0.227 9.552 ;
     RECT  0.084 9.552 0.227 9.576 ;
     RECT  0.06 9.576 0.227 9.648 ;
     RECT  0.084 9.648 0.227 9.672 ;
     RECT  0.06 9.672 0.227 9.744 ;
     RECT  0.084 9.744 0.227 9.768 ;
     RECT  0.06 9.768 0.227 9.84 ;
     RECT  0.084 9.84 0.227 9.864 ;
     RECT  0.06 9.864 0.227 9.936 ;
     RECT  0.084 9.936 0.227 9.96 ;
     RECT  0.06 9.96 0.227 10.032 ;
     RECT  0.084 10.032 0.227 10.056 ;
     RECT  0.06 10.056 0.227 10.128 ;
     RECT  0.084 10.128 0.227 10.152 ;
     RECT  0.06 10.152 0.227 10.224 ;
     RECT  0.084 10.224 0.227 10.248 ;
     RECT  0.227 9.456 0.371 10.248 ;
     RECT  0.371 9.504 2.408 10.248 ;
     RECT  0.325 14.976 2.408 15 ;
     RECT  0.181 16.32 2.408 16.344 ;
     RECT  2.408 2.148 2.512 27.552 ;
     RECT  2.512 2.418 2.6 27.552 ;
     RECT  2.6 2.418 2.704 27.822 ;
     RECT  2.704 9.504 2.839 9.576 ;
     RECT  2.839 9.504 4.129 9.528 ;
     RECT  4.129 9.504 5.108 10.104 ;
     RECT  2.704 14.976 5.108 15 ;
     RECT  2.704 16.32 5.108 16.344 ;
     RECT  5.108 2.148 5.212 27.552 ;
     RECT  5.212 2.418 5.3 27.552 ;
     RECT  5.3 2.418 5.404 27.822 ;
     RECT  5.404 9.504 7.808 10.104 ;
     RECT  5.404 14.976 7.808 15 ;
     RECT  5.404 16.32 7.808 16.344 ;
     RECT  7.808 2.148 7.912 27.552 ;
     RECT  7.912 2.418 8 27.552 ;
     RECT  8 2.418 8.104 27.822 ;
     RECT  8.104 9.504 10.508 10.104 ;
     RECT  8.104 14.976 10.508 15 ;
     RECT  8.104 16.32 10.508 16.344 ;
     RECT  10.508 2.148 10.612 27.552 ;
     RECT  10.612 2.418 10.7 27.552 ;
     RECT  10.7 2.418 10.804 27.822 ;
     RECT  10.804 9.504 13.208 10.104 ;
     RECT  10.804 14.976 13.208 15 ;
     RECT  10.804 16.32 13.208 16.344 ;
     RECT  13.208 2.148 13.312 27.552 ;
     RECT  13.312 2.418 13.4 27.552 ;
     RECT  13.4 2.418 13.504 27.822 ;
     RECT  13.504 9.504 15.908 10.104 ;
     RECT  15.289 13.632 15.908 13.656 ;
     RECT  13.504 14.976 15.908 15 ;
     RECT  13.504 16.32 15.908 16.344 ;
     RECT  15.908 2.148 16.012 27.552 ;
     RECT  16.012 2.418 16.1 27.552 ;
     RECT  16.1 2.418 16.204 27.822 ;
     RECT  16.204 9.504 16.595 10.104 ;
     RECT  16.204 13.104 16.633 13.656 ;
     RECT  16.204 27.6 16.645 27.822 ;
     RECT  16.645 27.6 17.317 28.776 ;
     RECT  16.204 22.848 17.509 24.264 ;
     RECT  16.633 13.632 17.948 13.656 ;
     RECT  16.204 14.976 17.948 15 ;
     RECT  17.948 13.632 17.989 15 ;
     RECT  16.204 16.32 17.989 16.344 ;
     RECT  17.317 27.216 17.989 28.776 ;
     RECT  17.989 13.632 18.061 15.24 ;
     RECT  17.509 22.848 18.421 24.552 ;
     RECT  17.989 27.216 18.421 29.352 ;
     RECT  17.989 16.32 18.457 17.112 ;
     RECT  18.421 27.216 18.457 30.072 ;
     RECT  18.421 22.752 18.469 24.552 ;
     RECT  16.204 7.152 18.608 7.176 ;
     RECT  16.595 9.504 18.608 9.528 ;
     RECT  18.061 13.632 18.608 15.288 ;
     RECT  18.457 16.32 18.608 17.448 ;
     RECT  18.469 22.752 18.608 25.032 ;
     RECT  18.457 26.88 18.608 30.072 ;
     RECT  18.608 2.148 18.712 30.072 ;
     RECT  18.712 2.418 18.904 30.072 ;
     RECT  18.904 26.544 19.09 30.072 ;
     RECT  19.09 26.544 19.189 30.12 ;
     RECT  18.904 13.584 19.253 17.448 ;
     RECT  19.189 26.544 19.322 30.072 ;
     RECT  19.253 13.632 20.089 17.448 ;
     RECT  18.904 22.752 20.293 25.272 ;
     RECT  19.322 26.544 20.293 29.352 ;
     RECT  20.089 17.424 20.333 17.448 ;
     RECT  20.089 13.632 20.492 16.344 ;
     RECT  20.293 22.752 20.869 29.352 ;
     RECT  18.904 7.056 21.308 7.08 ;
     RECT  20.492 12.912 21.308 16.344 ;
     RECT  20.437 17.616 21.308 17.64 ;
     RECT  20.869 22.704 21.308 29.352 ;
     RECT  21.308 2.148 21.412 29.352 ;
     RECT  21.412 2.418 21.604 29.352 ;
     RECT  21.604 13.008 21.773 17.64 ;
     RECT  21.604 21.648 21.989 23.88 ;
     RECT  21.604 25.056 22.321 27.624 ;
     RECT  21.773 13.008 22.741 13.944 ;
     RECT  21.989 22.752 22.777 23.88 ;
     RECT  21.989 21.648 22.853 21.672 ;
     RECT  21.773 14.976 22.883 17.64 ;
     RECT  22.777 22.752 23.281 24.216 ;
     RECT  23.281 22.032 23.605 24.216 ;
     RECT  22.321 25.488 23.605 27.624 ;
     RECT  21.604 7.056 23.893 7.08 ;
     RECT  23.893 7.056 24.008 7.176 ;
     RECT  21.604 8.256 24.008 8.28 ;
     RECT  22.741 12.96 24.008 13.944 ;
     RECT  22.883 14.976 24.008 16.44 ;
     RECT  22.883 17.616 24.008 17.64 ;
     RECT  23.605 22.032 24.008 27.624 ;
     RECT  24.008 2.148 24.112 27.624 ;
     RECT  24.112 2.418 24.2 27.624 ;
     RECT  21.604 28.752 24.2 29.352 ;
     RECT  24.2 2.418 24.304 29.352 ;
     RECT  24.304 13.104 24.445 16.536 ;
     RECT  24.304 28.752 24.764 29.352 ;
     RECT  24.304 20.592 24.905 21 ;
     RECT  24.304 22.032 25.085 27.624 ;
     RECT  24.764 28.752 25.309 30.168 ;
     RECT  25.309 28.752 25.379 30.072 ;
     RECT  24.304 11.76 25.477 11.784 ;
     RECT  24.304 18.192 25.484 18.888 ;
     RECT  24.445 13.104 25.505 16.344 ;
     RECT  25.505 13.104 25.525 16.536 ;
     RECT  25.484 18.144 25.525 18.888 ;
     RECT  25.477 11.76 25.573 11.976 ;
     RECT  25.525 13.104 25.573 17.16 ;
     RECT  25.525 18.144 25.625 19.224 ;
     RECT  25.085 22.032 25.657 24.456 ;
     RECT  25.573 11.76 26.125 17.16 ;
     RECT  25.625 18.144 26.125 18.456 ;
     RECT  25.657 21.984 26.125 24.456 ;
     RECT  25.085 25.44 26.125 27.624 ;
     RECT  24.905 20.592 26.485 20.616 ;
     RECT  26.125 21.984 26.485 27.624 ;
     RECT  24.304 7.152 26.708 7.176 ;
     RECT  24.304 8.256 26.708 8.28 ;
     RECT  26.125 10.608 26.708 10.632 ;
     RECT  26.125 11.76 26.708 18.456 ;
     RECT  26.485 20.592 26.708 27.624 ;
     RECT  26.708 2.148 26.812 27.624 ;
     RECT  26.812 2.418 26.9 27.624 ;
     RECT  25.379 28.752 26.9 29.352 ;
     RECT  26.9 2.418 27.004 29.352 ;
     RECT  27.004 10.272 27.155 17.16 ;
     RECT  27.004 8.256 27.209 9.144 ;
     RECT  27.004 18.192 27.389 18.456 ;
     RECT  27.004 28.752 27.821 29.352 ;
     RECT  27.004 20.496 27.929 27.624 ;
     RECT  27.155 13.008 28.069 17.16 ;
     RECT  27.389 18.192 28.069 18.216 ;
     RECT  27.155 10.272 28.249 10.296 ;
     RECT  27.155 11.76 28.357 11.784 ;
     RECT  28.069 13.008 28.357 18.216 ;
     RECT  28.249 10.032 29.005 10.296 ;
     RECT  29.005 10.032 29.077 10.68 ;
     RECT  28.357 11.76 29.077 18.216 ;
     RECT  29.077 10.032 29.185 18.216 ;
     RECT  29.185 10.032 29.257 18.792 ;
     RECT  28.825 19.872 29.257 19.896 ;
     RECT  27.004 7.152 29.408 7.176 ;
     RECT  27.209 8.256 29.408 8.28 ;
     RECT  29.257 10.032 29.408 19.896 ;
     RECT  27.929 20.928 29.408 27.624 ;
     RECT  29.408 2.148 29.512 27.624 ;
     RECT  29.512 2.418 29.6 27.624 ;
     RECT  27.821 28.752 29.6 28.776 ;
     RECT  29.6 2.418 29.704 28.776 ;
     RECT  29.704 7.056 29.945 16.344 ;
     RECT  29.704 17.472 29.945 20.568 ;
     RECT  29.945 7.056 30.275 15 ;
     RECT  30.275 7.056 30.316 8.28 ;
     RECT  30.275 9.36 30.323 15 ;
     RECT  29.704 21.648 30.419 27.624 ;
     RECT  29.945 19.776 30.46 20.568 ;
     RECT  29.945 17.472 30.521 18.792 ;
     RECT  29.945 15.984 30.665 16.344 ;
     RECT  30.521 18.192 30.737 18.792 ;
     RECT  30.316 7.056 30.809 7.176 ;
     RECT  30.46 19.776 30.881 20.328 ;
     RECT  30.316 8.16 31.417 8.28 ;
     RECT  30.323 9.36 31.417 9.672 ;
     RECT  30.809 7.152 31.453 7.176 ;
     RECT  31.417 8.16 31.453 9.672 ;
     RECT  30.881 20.304 31.633 20.328 ;
     RECT  30.419 21.696 31.633 27.624 ;
     RECT  30.665 16.32 31.777 16.344 ;
     RECT  31.777 16.32 31.993 16.584 ;
     RECT  30.737 18.192 31.993 18.216 ;
     RECT  31.453 7.152 32.108 9.672 ;
     RECT  30.323 10.656 32.108 15 ;
     RECT  31.993 16.32 32.108 18.216 ;
     RECT  31.633 20.304 32.108 27.624 ;
     RECT  32.108 2.148 32.212 27.624 ;
     RECT  32.212 2.418 32.3 27.624 ;
     RECT  29.704 28.752 32.3 28.776 ;
     RECT  32.3 2.418 32.404 28.776 ;
     RECT  32.404 10.656 32.531 16.584 ;
     RECT  32.404 18.192 32.645 27.624 ;
     RECT  32.645 19.392 33.149 27.624 ;
     RECT  32.645 18.192 33.577 18.216 ;
     RECT  32.404 7.152 33.596 9.528 ;
     RECT  32.531 10.656 33.596 16.344 ;
     RECT  33.149 19.392 33.689 20.088 ;
     RECT  33.577 17.616 33.865 18.216 ;
     RECT  33.596 7.152 33.937 16.344 ;
     RECT  33.865 17.616 33.937 18.84 ;
     RECT  33.689 19.92 34.801 20.088 ;
     RECT  33.149 21.12 34.801 27.624 ;
     RECT  33.937 7.152 34.808 18.84 ;
     RECT  34.801 19.92 34.808 27.624 ;
     RECT  34.808 2.148 34.912 27.624 ;
     RECT  34.912 2.418 35 27.624 ;
     RECT  32.404 28.752 35 28.776 ;
     RECT  35 2.418 35.104 28.776 ;
     RECT  35.104 7.152 35.201 17.64 ;
     RECT  35.201 8.208 35.273 17.64 ;
     RECT  35.104 19.632 35.417 27.624 ;
     RECT  35.417 20.64 36.137 27.624 ;
     RECT  36.137 20.736 36.179 27.624 ;
     RECT  35.104 28.752 36.353 28.776 ;
     RECT  35.417 19.632 36.601 19.656 ;
     RECT  35.201 7.152 37.033 7.176 ;
     RECT  35.273 8.208 37.033 17.16 ;
     RECT  37.033 7.152 37.045 17.16 ;
     RECT  37.045 7.152 37.508 17.256 ;
     RECT  36.601 18.768 37.508 19.656 ;
     RECT  36.179 20.832 37.508 27.624 ;
     RECT  37.508 2.148 37.612 27.624 ;
     RECT  37.612 2.418 37.7 27.624 ;
     RECT  37.7 2.418 37.804 27.822 ;
     RECT  37.804 18.768 37.901 18.792 ;
     RECT  37.804 5.712 38.117 17.16 ;
     RECT  38.117 5.712 39.085 15.864 ;
     RECT  38.117 16.896 39.085 17.16 ;
     RECT  37.804 20.928 39.161 27.624 ;
     RECT  39.161 20.928 39.197 27.192 ;
     RECT  39.197 20.928 39.308 27.096 ;
     RECT  39.308 20.448 39.697 27.096 ;
     RECT  39.445 30.144 39.737 30.168 ;
     RECT  39.229 18.768 39.769 18.792 ;
     RECT  39.697 19.872 39.769 27.096 ;
     RECT  39.085 5.712 40.208 17.16 ;
     RECT  39.769 18.768 40.208 27.096 ;
     RECT  40.208 2.148 40.312 27.552 ;
     RECT  40.312 2.418 40.4 27.552 ;
     RECT  40.4 2.418 40.504 27.822 ;
     RECT  40.504 5.856 41.033 17.112 ;
     RECT  40.705 30 41.033 30.024 ;
     RECT  41.033 10.656 41.069 17.112 ;
     RECT  40.504 20.496 41.285 26.904 ;
     RECT  41.285 20.496 41.501 26.808 ;
     RECT  41.137 30.048 41.537 30.168 ;
     RECT  40.504 4.848 41.557 4.872 ;
     RECT  41.033 5.856 41.557 9.624 ;
     RECT  41.557 4.848 41.645 9.624 ;
     RECT  41.501 20.496 41.929 26.616 ;
     RECT  41.537 30.144 42.077 30.168 ;
     RECT  41.929 20.304 42.325 26.616 ;
     RECT  41.645 4.848 42.908 9.288 ;
     RECT  41.069 10.656 42.908 17.016 ;
     RECT  42.901 18.144 42.908 18.168 ;
     RECT  42.325 19.536 42.908 26.616 ;
     RECT  42.908 2.148 43.012 27.552 ;
     RECT  43.012 2.418 43.1 27.552 ;
     RECT  43.1 2.418 43.204 27.822 ;
     RECT  43.204 10.656 43.301 16.344 ;
     RECT  43.204 5.136 44.269 7.176 ;
     RECT  43.204 8.208 44.269 9.576 ;
     RECT  43.301 10.656 44.269 14.76 ;
     RECT  43.301 15.744 44.269 16.344 ;
     RECT  44.269 5.136 44.3 9.576 ;
     RECT  43.204 17.712 44.305 26.616 ;
     RECT  44.3 4.512 44.387 9.576 ;
     RECT  44.387 5.184 44.525 9.576 ;
     RECT  44.269 10.656 44.732 16.344 ;
     RECT  44.305 17.664 44.845 26.616 ;
     RECT  44.845 17.664 45.025 26.808 ;
     RECT  44.525 5.184 45.608 9.528 ;
     RECT  44.732 10.56 45.608 16.344 ;
     RECT  45.025 17.472 45.608 26.808 ;
     RECT  45.608 2.148 45.712 27.552 ;
     RECT  45.712 2.418 45.8 27.552 ;
     RECT  45.8 2.418 45.904 27.822 ;
     RECT  45.904 4.656 46.019 7.224 ;
     RECT  45.904 8.256 46.361 26.664 ;
     RECT  45.904 3.408 46.787 3.432 ;
     RECT  46.361 8.256 46.865 18.984 ;
     RECT  46.361 20.16 46.933 26.664 ;
     RECT  46.933 20.16 47.005 26.808 ;
     RECT  47.005 20.16 47.041 26.904 ;
     RECT  46.019 4.656 47.261 5.208 ;
     RECT  46.019 6.336 47.401 7.224 ;
     RECT  46.865 8.256 47.401 16.536 ;
     RECT  47.401 6.336 47.468 16.536 ;
     RECT  47.468 6.24 47.833 16.536 ;
     RECT  46.865 17.712 47.833 18.984 ;
     RECT  47.041 20.16 48.085 27 ;
     RECT  47.261 5.184 48.121 5.208 ;
     RECT  47.833 6.24 48.121 18.984 ;
     RECT  48.085 20.064 48.121 27 ;
     RECT  48.193 3.936 48.308 3.96 ;
     RECT  48.121 5.184 48.308 27 ;
     RECT  48.308 2.148 48.412 27.552 ;
     RECT  48.412 2.418 48.5 27.552 ;
     RECT  48.5 2.418 48.604 27.822 ;
     RECT  48.604 10.08 48.844 27.192 ;
     RECT  48.844 10.08 49.133 15.912 ;
     RECT  48.844 17.04 49.133 27.192 ;
     RECT  48.604 5.952 49.676 9.096 ;
     RECT  49.133 10.08 49.676 14.52 ;
     RECT  49.133 15.552 49.885 15.912 ;
     RECT  49.133 17.04 49.885 17.64 ;
     RECT  49.741 2.832 49.916 2.856 ;
     RECT  49.916 2.832 49.957 3.576 ;
     RECT  49.676 5.952 49.961 14.52 ;
     RECT  49.957 2.832 50.003 4.104 ;
     RECT  49.885 15.552 50.101 17.64 ;
     RECT  49.133 18.624 50.101 27.192 ;
     RECT  50.003 4.08 50.245 4.104 ;
     RECT  50.245 4.08 51.008 4.44 ;
     RECT  49.961 6 51.008 14.52 ;
     RECT  50.101 15.552 51.008 27.192 ;
     RECT  51.008 2.148 51.112 27.552 ;
     RECT  51.112 2.418 51.2 27.552 ;
     RECT  51.2 2.418 51.304 27.822 ;
     RECT  51.304 6.288 51.443 14.52 ;
     RECT  51.304 4.416 51.545 5.064 ;
     RECT  51.304 20.16 51.545 27.192 ;
     RECT  51.304 15.552 51.725 17.688 ;
     RECT  51.304 3.312 51.923 3.336 ;
     RECT  51.545 20.16 52.441 27.144 ;
     RECT  51.545 4.512 52.453 5.064 ;
     RECT  52.453 4.512 52.46 5.16 ;
     RECT  52.46 4.512 52.499 5.736 ;
     RECT  51.304 18.768 52.513 18.84 ;
     RECT  52.441 20.112 52.513 27.144 ;
     RECT  52.499 4.752 52.547 5.736 ;
     RECT  51.725 15.552 52.801 17.496 ;
     RECT  52.513 18.768 52.909 27.144 ;
     RECT  52.547 4.752 53.557 5.16 ;
     RECT  51.443 6.768 53.665 14.52 ;
     RECT  52.801 15.552 53.665 17.688 ;
     RECT  53.557 4.416 53.708 5.16 ;
     RECT  53.665 6.768 53.708 17.688 ;
     RECT  52.909 18.768 53.708 27.336 ;
     RECT  53.708 2.148 53.812 27.552 ;
     RECT  53.812 2.418 53.9 27.552 ;
     RECT  53.9 2.418 54.004 27.822 ;
     RECT  54.004 4.416 54.101 16.68 ;
     RECT  54.004 17.76 54.173 27.192 ;
     RECT  54.173 17.76 54.821 25.512 ;
     RECT  54.101 4.752 54.857 16.68 ;
     RECT  54.821 20.4 54.857 25.512 ;
     RECT  54.857 4.896 54.893 16.68 ;
     RECT  54.893 4.896 55.361 16.296 ;
     RECT  54.173 26.88 55.361 27.192 ;
     RECT  54.821 17.76 55.501 19.368 ;
     RECT  54.857 21.12 55.545 25.512 ;
     RECT  54.004 3.312 55.82 3.336 ;
     RECT  55.361 4.896 55.82 14.952 ;
     RECT  55.82 3.312 56.408 14.952 ;
     RECT  55.361 16.272 56.408 16.296 ;
     RECT  55.501 17.424 56.408 19.368 ;
     RECT  55.545 21.12 56.408 25.56 ;
     RECT  55.361 27.168 56.408 27.192 ;
     RECT  56.408 2.148 56.512 27.552 ;
     RECT  56.512 2.418 56.6 27.552 ;
     RECT  56.6 2.418 56.704 27.822 ;
     RECT  56.704 8.976 56.729 18.84 ;
     RECT  56.729 18.144 56.765 18.84 ;
     RECT  56.704 20.304 56.867 25.752 ;
     RECT  56.704 5.424 56.945 7.992 ;
     RECT  56.729 8.976 56.981 17.064 ;
     RECT  56.945 5.568 57.089 7.992 ;
     RECT  56.765 18.144 57.593 18.456 ;
     RECT  57.089 6.288 57.629 7.992 ;
     RECT  56.981 8.976 57.737 15.816 ;
     RECT  56.867 20.304 57.829 25.56 ;
     RECT  57.593 18.432 57.837 18.456 ;
     RECT  57.737 10.848 57.875 15.816 ;
     RECT  57.875 12.768 57.881 15.816 ;
     RECT  56.981 17.04 58.061 17.064 ;
     RECT  57.629 6.288 58.117 7.416 ;
     RECT  57.829 19.536 58.237 25.56 ;
     RECT  57.737 8.976 58.849 9.864 ;
     RECT  57.875 10.848 58.849 11.784 ;
     RECT  58.849 8.976 59.029 11.784 ;
     RECT  57.881 12.768 59.029 13.944 ;
     RECT  56.704 3.936 59.108 3.96 ;
     RECT  58.117 5.616 59.108 7.416 ;
     RECT  59.029 8.976 59.108 13.944 ;
     RECT  57.881 14.928 59.108 15.816 ;
     RECT  58.237 19.536 59.108 26.136 ;
     RECT  56.704 27.168 59.108 27.192 ;
     RECT  59.108 2.148 59.212 27.552 ;
     RECT  59.212 2.418 59.3 27.552 ;
     RECT  59.3 2.418 59.404 27.822 ;
     RECT  59.404 6.672 59.465 8.184 ;
     RECT  59.404 9.264 59.681 12.888 ;
     RECT  59.681 9.264 59.891 12.552 ;
     RECT  59.891 10.848 59.897 12.552 ;
     RECT  59.404 19.776 59.897 20.712 ;
     RECT  59.891 9.264 59.933 9.864 ;
     RECT  59.404 14.928 59.969 17.112 ;
     RECT  59.933 9.84 60.005 9.864 ;
     RECT  59.897 11.136 60.005 12.552 ;
     RECT  59.969 14.928 60.041 15.576 ;
     RECT  59.404 21.984 60.265 25.704 ;
     RECT  60.265 21.984 60.316 25.512 ;
     RECT  59.465 6.816 60.365 8.184 ;
     RECT  60.005 11.136 60.365 11.976 ;
     RECT  60.365 6.816 60.371 6.84 ;
     RECT  60.365 7.92 60.371 8.184 ;
     RECT  59.897 20.544 60.397 20.712 ;
     RECT  60.316 21.984 60.397 24.36 ;
     RECT  60.365 11.376 60.473 11.976 ;
     RECT  60.397 20.544 60.473 24.36 ;
     RECT  60.473 20.544 60.509 24.168 ;
     RECT  60.473 11.424 60.545 11.784 ;
     RECT  60.041 14.928 60.581 14.952 ;
     RECT  60.509 21.984 60.653 24.168 ;
     RECT  59.969 16.56 60.997 17.112 ;
     RECT  60.316 25.488 61.513 25.512 ;
     RECT  61.513 25.248 61.693 25.512 ;
     RECT  60.371 7.92 61.808 7.944 ;
     RECT  60.545 11.76 61.808 11.784 ;
     RECT  60.997 16.416 61.808 17.688 ;
     RECT  60.509 20.928 61.808 20.952 ;
     RECT  60.653 21.984 61.808 23.64 ;
     RECT  61.693 25.008 61.808 25.512 ;
     RECT  61.808 2.148 61.912 27.552 ;
     RECT  61.912 2.418 62 27.552 ;
     RECT  62 2.418 62.104 27.822 ;
     RECT  62.104 7.056 63.277 9.768 ;
     RECT  62.104 10.992 63.277 12.84 ;
     RECT  62.104 19.92 63.277 20.904 ;
     RECT  62.104 22.08 63.277 25.896 ;
     RECT  63.277 19.92 63.349 25.896 ;
     RECT  63.277 6.864 63.853 12.84 ;
     RECT  63.853 6.864 64.692 6.888 ;
     RECT  63.853 6.888 64.716 6.96 ;
     RECT  63.853 6.96 64.692 6.984 ;
     RECT  63.853 6.984 64.716 7.056 ;
     RECT  63.853 7.056 64.692 7.08 ;
     RECT  63.853 7.08 64.716 7.152 ;
     RECT  63.853 7.152 64.692 7.176 ;
     RECT  63.853 7.176 64.716 7.248 ;
     RECT  63.853 7.248 64.692 7.272 ;
     RECT  63.853 7.272 64.716 7.344 ;
     RECT  63.853 7.344 64.692 7.368 ;
     RECT  63.853 7.368 64.716 7.44 ;
     RECT  63.853 7.44 64.692 7.464 ;
     RECT  63.853 7.464 64.716 7.536 ;
     RECT  63.853 7.536 64.692 7.56 ;
     RECT  63.853 7.56 64.716 7.632 ;
     RECT  63.853 7.632 64.692 7.656 ;
     RECT  63.853 7.656 64.716 7.728 ;
     RECT  63.853 7.728 64.692 7.752 ;
     RECT  63.853 7.752 64.716 7.824 ;
     RECT  63.853 7.824 64.692 7.848 ;
     RECT  63.853 7.848 64.716 7.92 ;
     RECT  63.853 7.92 64.692 7.944 ;
     RECT  63.853 7.944 64.716 8.016 ;
     RECT  63.853 8.016 64.692 8.04 ;
     RECT  63.853 8.04 64.716 8.112 ;
     RECT  63.853 8.112 64.692 8.136 ;
     RECT  63.853 8.136 64.716 8.208 ;
     RECT  63.853 8.208 64.692 8.232 ;
     RECT  63.853 8.232 64.716 8.304 ;
     RECT  63.853 8.304 64.692 8.328 ;
     RECT  63.853 8.328 64.716 8.4 ;
     RECT  63.853 8.4 64.692 8.424 ;
     RECT  63.853 8.424 64.716 8.496 ;
     RECT  63.853 8.496 64.692 8.52 ;
     RECT  63.853 8.52 64.716 8.592 ;
     RECT  63.853 8.592 64.692 8.616 ;
     RECT  63.853 8.616 64.716 8.688 ;
     RECT  63.853 8.688 64.692 8.712 ;
     RECT  63.853 8.712 64.716 8.784 ;
     RECT  63.853 8.784 64.692 8.808 ;
     RECT  63.853 8.808 64.716 8.88 ;
     RECT  63.853 8.88 64.692 8.904 ;
     RECT  63.853 8.904 64.716 8.976 ;
     RECT  63.853 8.976 64.692 9 ;
     RECT  63.853 9 64.716 9.072 ;
     RECT  63.853 9.072 64.692 9.096 ;
     RECT  63.853 9.096 64.716 9.168 ;
     RECT  63.853 9.168 64.692 9.192 ;
     RECT  63.853 9.192 64.716 9.264 ;
     RECT  63.853 9.264 64.692 9.288 ;
     RECT  63.853 9.288 64.716 9.36 ;
     RECT  63.853 9.36 64.692 9.384 ;
     RECT  63.853 9.384 64.716 9.456 ;
     RECT  63.853 9.456 64.692 9.48 ;
     RECT  63.853 9.48 64.716 9.552 ;
     RECT  63.853 9.552 64.692 9.576 ;
     RECT  63.853 9.576 64.716 9.648 ;
     RECT  63.853 9.648 64.692 9.672 ;
     RECT  63.853 9.672 64.716 9.744 ;
     RECT  63.853 9.744 64.692 9.768 ;
     RECT  63.853 9.768 64.716 9.84 ;
     RECT  63.853 9.84 64.692 9.864 ;
     RECT  63.853 9.864 64.716 9.936 ;
     RECT  63.853 9.936 64.692 9.96 ;
     RECT  63.853 9.96 64.716 10.032 ;
     RECT  63.853 10.032 64.692 10.056 ;
     RECT  63.853 10.056 64.716 10.128 ;
     RECT  63.853 10.128 64.692 10.152 ;
     RECT  63.853 10.152 64.716 10.224 ;
     RECT  63.853 10.224 64.692 10.248 ;
     RECT  63.853 10.248 64.716 10.32 ;
     RECT  63.853 10.32 64.692 10.344 ;
     RECT  63.853 10.344 64.716 10.416 ;
     RECT  63.853 10.416 64.692 10.44 ;
     RECT  63.853 10.44 64.716 10.512 ;
     RECT  63.853 10.512 64.692 10.536 ;
     RECT  63.853 10.536 64.716 10.608 ;
     RECT  63.853 10.608 64.692 10.632 ;
     RECT  63.853 10.632 64.716 10.704 ;
     RECT  63.853 10.704 64.692 10.728 ;
     RECT  63.853 10.728 64.716 10.8 ;
     RECT  63.853 10.8 64.692 10.824 ;
     RECT  63.853 10.824 64.716 10.896 ;
     RECT  63.853 10.896 64.692 10.92 ;
     RECT  63.853 10.92 64.716 10.992 ;
     RECT  63.853 10.992 64.692 11.016 ;
     RECT  63.853 11.016 64.716 11.088 ;
     RECT  63.853 11.088 64.692 11.112 ;
     RECT  63.853 11.112 64.716 11.184 ;
     RECT  63.853 11.184 64.692 11.208 ;
     RECT  63.853 11.208 64.716 11.28 ;
     RECT  63.853 11.28 64.692 11.304 ;
     RECT  63.853 11.304 64.716 11.376 ;
     RECT  63.853 11.376 64.692 11.4 ;
     RECT  63.853 11.4 64.716 11.472 ;
     RECT  63.853 11.472 64.692 11.496 ;
     RECT  63.853 11.496 64.716 11.568 ;
     RECT  63.853 11.568 64.692 11.592 ;
     RECT  63.853 11.592 64.716 11.664 ;
     RECT  63.853 11.664 64.692 11.688 ;
     RECT  63.853 11.688 64.716 11.76 ;
     RECT  63.853 11.76 64.692 11.784 ;
     RECT  63.853 11.784 64.716 11.856 ;
     RECT  63.853 11.856 64.692 11.88 ;
     RECT  63.853 11.88 64.716 11.952 ;
     RECT  63.853 11.952 64.692 11.976 ;
     RECT  63.853 11.976 64.716 12.048 ;
     RECT  63.853 12.048 64.692 12.072 ;
     RECT  63.853 12.072 64.716 12.144 ;
     RECT  63.853 12.144 64.692 12.168 ;
     RECT  63.853 12.168 64.716 12.24 ;
     RECT  63.853 12.24 64.692 12.264 ;
     RECT  63.853 12.264 64.716 12.336 ;
     RECT  63.853 12.336 64.692 12.36 ;
     RECT  63.853 12.36 64.716 12.432 ;
     RECT  63.853 12.432 64.692 12.456 ;
     RECT  63.853 12.456 64.716 12.528 ;
     RECT  63.853 12.528 64.692 12.552 ;
     RECT  63.853 12.552 64.716 12.624 ;
     RECT  63.853 12.624 64.692 12.648 ;
     RECT  63.853 12.648 64.716 12.72 ;
     RECT  63.853 12.72 64.692 12.744 ;
     RECT  63.853 12.744 64.716 12.816 ;
     RECT  63.853 12.816 64.692 12.84 ;
     RECT  63.853 12.84 64.716 12.912 ;
     RECT  63.853 12.912 64.692 12.936 ;
     RECT  63.349 19.92 64.692 19.944 ;
     RECT  63.349 19.944 64.716 20.016 ;
     RECT  63.349 20.016 64.692 20.04 ;
     RECT  63.349 20.04 64.716 20.112 ;
     RECT  63.349 20.112 64.692 20.136 ;
     RECT  63.349 20.136 64.716 20.208 ;
     RECT  63.349 20.208 64.692 20.232 ;
     RECT  63.349 20.232 64.716 20.304 ;
     RECT  63.349 20.304 64.692 20.328 ;
     RECT  63.349 20.328 64.716 20.4 ;
     RECT  63.349 20.4 64.692 20.424 ;
     RECT  63.349 20.424 64.716 20.496 ;
     RECT  63.349 20.496 64.692 20.52 ;
     RECT  63.349 20.52 64.716 20.592 ;
     RECT  63.349 20.592 64.692 20.616 ;
     RECT  63.349 20.616 64.716 20.688 ;
     RECT  63.349 20.688 64.692 20.712 ;
     RECT  63.349 20.712 64.716 20.784 ;
     RECT  63.349 20.784 64.692 20.808 ;
     RECT  63.349 20.808 64.716 20.88 ;
     RECT  63.349 20.88 64.692 20.904 ;
     RECT  63.349 20.904 64.716 20.976 ;
     RECT  63.349 20.976 64.692 21 ;
     RECT  63.349 21 64.716 21.072 ;
     RECT  63.349 21.072 64.692 21.096 ;
     RECT  63.349 21.096 64.716 21.168 ;
     RECT  63.349 21.168 64.692 21.192 ;
     RECT  63.349 21.192 64.716 21.264 ;
     RECT  63.349 21.264 64.692 21.288 ;
     RECT  63.349 21.288 64.716 21.36 ;
     RECT  63.349 21.36 64.692 21.384 ;
     RECT  63.349 21.384 64.716 21.456 ;
     RECT  63.349 21.456 64.692 21.48 ;
     RECT  63.349 21.48 64.716 21.552 ;
     RECT  63.349 21.552 64.692 21.576 ;
     RECT  63.349 21.576 64.716 21.648 ;
     RECT  63.349 21.648 64.692 21.672 ;
     RECT  63.349 21.672 64.716 21.744 ;
     RECT  63.349 21.744 64.692 21.768 ;
     RECT  63.349 21.768 64.716 21.84 ;
     RECT  63.349 21.84 64.692 21.864 ;
     RECT  63.349 21.864 64.716 21.936 ;
     RECT  63.349 21.936 64.692 21.96 ;
     RECT  63.349 21.96 64.716 22.032 ;
     RECT  63.349 22.032 64.692 22.056 ;
     RECT  63.349 22.056 64.716 22.128 ;
     RECT  63.349 22.128 64.692 22.152 ;
     RECT  63.349 22.152 64.716 22.224 ;
     RECT  63.349 22.224 64.692 22.248 ;
     RECT  63.349 22.248 64.716 22.32 ;
     RECT  63.349 22.32 64.692 22.344 ;
     RECT  63.349 22.344 64.716 22.416 ;
     RECT  63.349 22.416 64.692 22.44 ;
     RECT  63.349 22.44 64.716 22.512 ;
     RECT  63.349 22.512 64.692 22.536 ;
     RECT  63.349 22.536 64.716 22.608 ;
     RECT  63.349 22.608 64.692 22.632 ;
     RECT  63.349 22.632 64.716 22.704 ;
     RECT  63.349 22.704 64.692 22.728 ;
     RECT  63.349 22.728 64.716 22.8 ;
     RECT  63.349 22.8 64.692 22.824 ;
     RECT  63.349 22.824 64.716 22.896 ;
     RECT  63.349 22.896 64.692 22.92 ;
     RECT  63.349 22.92 64.716 22.992 ;
     RECT  63.349 22.992 64.692 23.016 ;
     RECT  63.349 23.016 64.716 23.088 ;
     RECT  63.349 23.088 64.692 23.112 ;
     RECT  63.349 23.112 64.716 23.184 ;
     RECT  63.349 23.184 64.692 23.208 ;
     RECT  63.349 23.208 64.716 23.28 ;
     RECT  63.349 23.28 64.692 23.304 ;
     RECT  63.349 23.304 64.716 23.376 ;
     RECT  63.349 23.376 64.692 23.4 ;
     RECT  63.349 23.4 64.716 23.472 ;
     RECT  63.349 23.472 64.692 23.496 ;
     RECT  63.349 23.496 64.716 23.568 ;
     RECT  63.349 23.568 64.692 23.592 ;
     RECT  63.349 23.592 64.716 23.664 ;
     RECT  63.349 23.664 64.692 23.688 ;
     RECT  63.349 23.688 64.716 23.76 ;
     RECT  63.349 23.76 64.692 23.784 ;
     RECT  63.349 23.784 64.716 23.856 ;
     RECT  63.349 23.856 64.692 23.88 ;
     RECT  63.349 23.88 64.716 23.952 ;
     RECT  63.349 23.952 64.692 23.976 ;
     RECT  63.349 23.976 64.716 24.048 ;
     RECT  63.349 24.048 64.692 24.072 ;
     RECT  63.349 24.072 64.716 24.144 ;
     RECT  63.349 24.144 64.692 24.168 ;
     RECT  63.349 24.168 64.716 24.24 ;
     RECT  63.349 24.24 64.692 24.264 ;
     RECT  63.349 24.264 64.716 24.336 ;
     RECT  63.349 24.336 64.692 24.36 ;
     RECT  63.349 24.36 64.716 24.432 ;
     RECT  63.349 24.432 64.692 24.456 ;
     RECT  63.349 24.456 64.716 24.528 ;
     RECT  63.349 24.528 64.692 24.552 ;
     RECT  63.349 24.552 64.716 24.624 ;
     RECT  63.349 24.624 64.692 24.648 ;
     RECT  63.349 24.648 64.716 24.72 ;
     RECT  63.349 24.72 64.692 24.744 ;
     RECT  63.349 24.744 64.716 24.816 ;
     RECT  63.349 24.816 64.692 24.84 ;
     RECT  63.349 24.84 64.716 24.912 ;
     RECT  63.349 24.912 64.692 24.936 ;
     RECT  63.349 24.936 64.716 25.008 ;
     RECT  63.349 25.008 64.692 25.032 ;
     RECT  63.349 25.032 64.716 25.104 ;
     RECT  63.349 25.104 64.692 25.128 ;
     RECT  63.349 25.128 64.716 25.2 ;
     RECT  63.349 25.2 64.692 25.224 ;
     RECT  63.349 25.224 64.716 25.296 ;
     RECT  63.349 25.296 64.692 25.32 ;
     RECT  63.349 25.32 64.716 25.392 ;
     RECT  63.349 25.392 64.692 25.416 ;
     RECT  63.349 25.416 64.716 25.488 ;
     RECT  63.349 25.488 64.692 25.512 ;
     RECT  63.349 25.512 64.716 25.584 ;
     RECT  63.349 25.584 64.692 25.608 ;
     RECT  63.349 25.608 64.716 25.68 ;
     RECT  63.349 25.68 64.692 25.704 ;
     RECT  63.349 25.704 64.716 25.776 ;
     RECT  63.349 25.776 64.692 25.8 ;
     RECT  63.349 25.8 64.716 25.872 ;
     RECT  63.349 25.872 64.692 25.896 ;
     RECT  63.349 25.896 64.716 25.968 ;
     RECT  63.349 25.968 64.692 25.992 ;
     RECT  64.716 22.08 64.757 22.104 ;
    LAYER M5 ;
     RECT  2.4 2.137 2.52 2.151 ;
     RECT  5.1 2.137 5.22 2.151 ;
     RECT  7.8 2.137 7.92 2.151 ;
     RECT  10.5 2.137 10.62 2.151 ;
     RECT  13.2 2.137 13.32 2.151 ;
     RECT  15.9 2.137 16.02 2.151 ;
     RECT  18.6 2.137 18.72 2.151 ;
     RECT  21.3 2.137 21.42 2.151 ;
     RECT  24 2.137 24.12 2.151 ;
     RECT  26.7 2.137 26.82 2.151 ;
     RECT  29.4 2.137 29.52 2.151 ;
     RECT  32.1 2.137 32.22 2.151 ;
     RECT  34.8 2.137 34.92 2.151 ;
     RECT  37.5 2.137 37.62 2.151 ;
     RECT  40.2 2.137 40.32 2.151 ;
     RECT  42.9 2.137 43.02 2.151 ;
     RECT  45.6 2.137 45.72 2.151 ;
     RECT  48.3 2.137 48.42 2.151 ;
     RECT  51 2.137 51.12 2.151 ;
     RECT  53.7 2.137 53.82 2.151 ;
     RECT  56.4 2.137 56.52 2.151 ;
     RECT  59.1 2.137 59.22 2.151 ;
     RECT  61.8 2.137 61.92 2.151 ;
     RECT  51 2.151 51.312 3.301 ;
     RECT  56.4 2.151 56.712 3.301 ;
     RECT  45.6 2.151 45.912 3.397 ;
     RECT  49.968 2.821 49.992 4.115 ;
     RECT  55.872 3.301 56.712 4.115 ;
     RECT  51 3.301 51.912 4.501 ;
     RECT  51 4.501 52.488 4.547 ;
     RECT  53.7 2.151 54.012 4.693 ;
     RECT  52.464 4.547 52.488 5.029 ;
     RECT  53.568 4.693 54.012 5.077 ;
     RECT  44.352 4.501 44.376 5.171 ;
     RECT  52.464 5.029 52.536 5.171 ;
     RECT  45.6 3.397 46.776 5.219 ;
     RECT  59.1 2.151 59.412 5.605 ;
     RECT  52.512 5.171 52.536 5.747 ;
     RECT  45.6 5.219 46.008 5.941 ;
     RECT  42.9 2.151 43.212 6.037 ;
     RECT  48.3 2.151 48.612 6.181 ;
     RECT  45.12 5.941 46.008 6.229 ;
     RECT  48.3 6.181 48.936 6.229 ;
     RECT  41.568 4.837 41.592 6.275 ;
     RECT  51 4.547 51.432 6.323 ;
     RECT  58.128 5.605 59.412 6.371 ;
     RECT  40.2 2.151 40.512 6.613 ;
     RECT  40.2 6.613 41.496 6.805 ;
     RECT  56.256 4.115 56.712 6.805 ;
     RECT  59.1 6.371 59.412 6.805 ;
     RECT  44.688 6.229 46.008 6.899 ;
     RECT  47.52 6.229 48.936 6.899 ;
     RECT  24 2.151 24.312 7.045 ;
     RECT  53.568 5.077 54.552 7.093 ;
     RECT  56.256 6.805 57.336 7.093 ;
     RECT  38.976 6.805 41.496 7.139 ;
     RECT  15.9 2.151 16.212 7.141 ;
     RECT  23.904 7.045 24.312 7.187 ;
     RECT  53.184 7.093 54.552 7.283 ;
     RECT  47.52 6.899 48.744 7.381 ;
     RECT  51 6.323 51.312 7.381 ;
     RECT  34.8 2.151 35.112 7.429 ;
     RECT  42.768 6.037 43.212 7.475 ;
     RECT  38.976 7.139 40.512 7.715 ;
     RECT  29.4 2.151 29.712 7.909 ;
     RECT  37.5 2.151 37.812 7.909 ;
     RECT  47.424 7.381 48.744 8.051 ;
     RECT  47.424 8.051 48.612 8.147 ;
     RECT  29.4 7.909 30.264 8.149 ;
     RECT  59.1 6.805 60.36 8.195 ;
     RECT  21.3 2.151 21.612 8.245 ;
     RECT  55.632 7.093 57.336 8.435 ;
     RECT  34.704 7.429 35.112 8.437 ;
     RECT  34.704 8.437 36.072 8.485 ;
     RECT  37.056 7.909 37.812 8.485 ;
     RECT  51 7.381 51.912 8.485 ;
     RECT  55.824 8.435 57.336 9.011 ;
     RECT  26.7 2.151 27.012 9.109 ;
     RECT  39.312 7.715 40.512 9.155 ;
     RECT  51 8.485 52.488 9.205 ;
     RECT  53.568 7.283 54.552 9.205 ;
     RECT  51 9.205 54.552 9.251 ;
     RECT  41.808 7.765 41.832 9.299 ;
     RECT  34.368 8.485 37.812 9.349 ;
     RECT  0.192 9.349 0.216 9.445 ;
     RECT  18.6 2.151 18.912 9.493 ;
     RECT  29.4 8.149 30.84 9.683 ;
     RECT  49.728 9.013 49.752 9.779 ;
     RECT  33.936 9.349 37.812 9.925 ;
     RECT  55.824 9.011 56.712 10.019 ;
     RECT  40.2 9.155 40.512 10.213 ;
     RECT  47.568 8.147 48.612 10.213 ;
     RECT  29.4 9.683 30.312 10.261 ;
     RECT  40.2 10.213 41.016 10.741 ;
     RECT  59.1 8.195 59.412 10.741 ;
     RECT  33.648 9.925 37.812 10.835 ;
     RECT  29.28 10.261 30.312 10.883 ;
     RECT  40.2 10.741 41.544 10.883 ;
     RECT  47.088 10.213 48.612 10.883 ;
     RECT  59.1 10.741 59.88 10.883 ;
     RECT  56.4 10.019 56.712 10.933 ;
     RECT  52.464 9.251 54.552 10.979 ;
     RECT  29.4 10.883 30.312 11.029 ;
     RECT  53.568 10.979 54.552 11.173 ;
     RECT  52.464 10.979 52.488 11.219 ;
     RECT  41.52 10.883 41.544 11.365 ;
     RECT  44.688 6.899 45.912 11.701 ;
     RECT  24 7.187 24.312 11.749 ;
     RECT  29.4 11.029 30.84 11.893 ;
     RECT  24 11.749 25.272 11.941 ;
     RECT  26.7 9.109 27.144 11.941 ;
     RECT  29.088 11.893 30.84 11.987 ;
     RECT  56.4 10.933 56.904 11.987 ;
     RECT  53.568 11.173 54.936 12.035 ;
     RECT  40.2 10.883 40.512 12.037 ;
     RECT  41.52 11.365 41.832 12.227 ;
     RECT  41.52 12.227 41.544 12.323 ;
     RECT  24 11.941 27.144 12.371 ;
     RECT  42.9 7.475 43.212 12.469 ;
     RECT  33.936 10.835 37.812 12.517 ;
     RECT  44.688 11.701 46.296 12.517 ;
     RECT  24 12.371 27.012 12.755 ;
     RECT  21.3 8.245 22.488 12.901 ;
     RECT  20.544 12.901 22.488 12.949 ;
     RECT  20.544 12.949 22.776 12.997 ;
     RECT  24 12.755 25.608 12.997 ;
     RECT  29.088 11.987 30.312 13.043 ;
     RECT  51 9.251 51.312 13.045 ;
     RECT  15.9 7.141 16.584 13.139 ;
     RECT  44.496 12.517 46.296 13.139 ;
     RECT  47.568 10.883 48.612 13.333 ;
     RECT  44.496 13.139 45.912 13.379 ;
     RECT  42.768 12.469 43.212 13.427 ;
     RECT  50.16 13.045 51.312 13.477 ;
     RECT  20.544 12.997 25.608 13.667 ;
     RECT  33.936 12.517 38.328 13.667 ;
     RECT  33.936 13.667 37.812 13.669 ;
     RECT  33.888 13.669 37.812 13.715 ;
     RECT  29.4 13.043 30.312 13.763 ;
     RECT  50.16 13.477 52.296 13.859 ;
     RECT  53.7 12.035 54.936 13.907 ;
     RECT  20.544 13.667 21.612 14.197 ;
     RECT  51 13.859 52.296 14.339 ;
     RECT  18 9.493 18.912 14.389 ;
     RECT  20.016 14.197 21.612 14.389 ;
     RECT  39.792 12.037 40.512 14.435 ;
     RECT  36.144 13.715 37.812 14.675 ;
     RECT  29.4 13.763 29.928 14.677 ;
     RECT  33.888 13.715 35.112 14.725 ;
     RECT  36.144 14.675 36.168 14.725 ;
     RECT  28.752 14.677 29.928 14.771 ;
     RECT  18 14.389 21.612 14.867 ;
     RECT  53.7 13.907 54.696 14.963 ;
     RECT  0.192 9.445 0.36 15.011 ;
     RECT  45.6 13.379 45.912 15.013 ;
     RECT  18 14.867 20.04 15.251 ;
     RECT  18.6 15.251 20.04 15.299 ;
     RECT  32.1 2.151 32.412 15.301 ;
     RECT  33.888 14.725 36.168 15.301 ;
     RECT  59.1 10.883 59.412 15.349 ;
     RECT  22.752 13.667 25.608 15.443 ;
     RECT  28.752 14.771 29.832 15.443 ;
     RECT  44.496 13.379 44.52 15.491 ;
     RECT  21.3 14.867 21.612 15.493 ;
     RECT  22.752 15.443 22.872 15.493 ;
     RECT  56.4 11.987 56.712 15.589 ;
     RECT  57.84 12.325 57.864 15.589 ;
     RECT  42.9 13.427 43.212 15.685 ;
     RECT  24 15.443 25.608 15.875 ;
     RECT  42.768 15.685 43.212 15.971 ;
     RECT  29.4 15.443 29.832 16.019 ;
     RECT  32.1 15.301 36.168 16.019 ;
     RECT  45.6 15.013 46.152 16.019 ;
     RECT  59.1 15.349 59.832 16.259 ;
     RECT  0.192 15.011 0.216 16.355 ;
     RECT  47.568 13.333 48.792 16.355 ;
     RECT  33.888 16.019 36.168 16.405 ;
     RECT  37.5 14.675 37.812 16.405 ;
     RECT  61.8 2.151 62.112 16.405 ;
     RECT  29.4 16.019 29.712 16.501 ;
     RECT  32.1 16.019 32.52 16.595 ;
     RECT  18.6 15.299 19.032 16.933 ;
     RECT  20.016 15.299 20.04 16.933 ;
     RECT  56.4 15.589 57.864 17.075 ;
     RECT  18.6 16.933 20.04 17.123 ;
     RECT  21.3 15.493 22.872 17.123 ;
     RECT  40.08 14.435 40.512 17.171 ;
     RECT  48.3 16.355 48.792 17.173 ;
     RECT  33.888 16.405 37.812 17.267 ;
     RECT  18.6 17.123 19.512 17.459 ;
     RECT  28.656 16.501 29.712 17.461 ;
     RECT  56.4 17.075 56.712 17.509 ;
     RECT  48.3 17.173 48.984 17.603 ;
     RECT  24 15.875 25.56 17.605 ;
     RECT  51 14.339 51.312 17.605 ;
     RECT  21.3 17.123 21.912 17.651 ;
     RECT  61.008 16.405 62.112 17.699 ;
     RECT  53.7 14.963 54.012 17.893 ;
     RECT  45.6 16.019 46.008 18.181 ;
     RECT  28.656 17.461 30.216 18.227 ;
     RECT  29.4 18.227 30.216 18.275 ;
     RECT  57.84 17.075 57.864 18.421 ;
     RECT  55.728 17.509 56.712 18.755 ;
     RECT  33.888 17.267 36.168 18.757 ;
     RECT  37.5 17.267 37.812 18.757 ;
     RECT  45.6 18.181 46.152 18.803 ;
     RECT  33.888 18.757 37.812 18.851 ;
     RECT  52.656 17.029 52.68 18.851 ;
     RECT  53.7 17.893 54.36 18.851 ;
     RECT  23.04 17.605 25.56 19.235 ;
     RECT  48.3 17.603 48.792 19.237 ;
     RECT  57.744 18.421 57.864 19.525 ;
     RECT  29.4 18.275 29.712 19.765 ;
     RECT  53.7 18.851 54.012 19.861 ;
     RECT  34.8 18.851 37.812 19.909 ;
     RECT  44.352 18.565 44.376 20.003 ;
     RECT  45.6 18.803 45.912 20.101 ;
     RECT  48.3 19.237 49.416 20.291 ;
     RECT  40.2 17.171 40.512 20.437 ;
     RECT  26.7 12.755 27.012 20.485 ;
     RECT  56.4 18.755 56.712 21.109 ;
     RECT  26.7 20.485 27.384 21.155 ;
     RECT  34.08 19.909 37.812 21.155 ;
     RECT  39.36 20.437 40.512 21.155 ;
     RECT  46.944 20.293 46.968 21.155 ;
     RECT  57.744 19.525 57.96 21.155 ;
     RECT  32.1 16.595 32.412 21.541 ;
     RECT  50.88 17.605 51.312 21.541 ;
     RECT  44.448 20.101 45.912 21.637 ;
     RECT  29.4 19.765 30.408 21.683 ;
     RECT  57.936 21.155 57.96 21.683 ;
     RECT  48.3 20.291 48.888 21.829 ;
     RECT  53.7 19.861 54.12 21.875 ;
     RECT  48.3 21.829 49.08 22.021 ;
     RECT  29.4 21.683 29.712 22.069 ;
     RECT  48.3 22.021 49.896 22.163 ;
     RECT  59.1 16.259 59.412 22.165 ;
     RECT  31.872 21.541 32.412 22.259 ;
     RECT  41.904 21.541 41.928 22.451 ;
     RECT  21.3 17.651 21.612 22.693 ;
     RECT  18.6 17.459 18.912 22.741 ;
     RECT  59.1 22.165 59.544 22.741 ;
     RECT  15.9 13.139 16.212 22.837 ;
     RECT  55.44 21.109 56.712 23.029 ;
     RECT  55.44 23.029 56.856 23.077 ;
     RECT  18.432 22.741 18.912 23.125 ;
     RECT  58.992 22.741 59.544 23.125 ;
     RECT  29.28 22.069 29.712 23.221 ;
     RECT  38.976 22.741 39 23.269 ;
     RECT  38.784 23.269 39 23.315 ;
     RECT  58.992 23.125 60.216 23.605 ;
     RECT  15.9 22.837 16.488 23.701 ;
     RECT  34.8 21.155 36.024 23.701 ;
     RECT  15.9 23.701 16.968 23.845 ;
     RECT  18.384 23.125 18.912 23.845 ;
     RECT  42.9 15.971 43.212 23.845 ;
     RECT  48.3 22.163 49.08 23.891 ;
     RECT  23.04 19.235 25.368 23.987 ;
     RECT  38.784 23.315 38.808 24.035 ;
     RECT  58.656 23.605 60.264 24.131 ;
     RECT  20.88 22.693 21.612 24.229 ;
     RECT  37.5 21.155 37.812 24.325 ;
     RECT  26.7 21.155 27.012 24.469 ;
     RECT  55.44 23.077 57.624 24.563 ;
     RECT  29.04 23.221 29.712 24.611 ;
     RECT  48.3 23.891 48.792 24.611 ;
     RECT  44.304 21.637 45.912 24.805 ;
     RECT  59.1 24.131 60.264 24.899 ;
     RECT  20.352 24.229 21.612 25.045 ;
     RECT  40.2 21.155 40.512 25.045 ;
     RECT  34.272 23.701 36.024 25.091 ;
     RECT  42.48 23.845 43.212 25.139 ;
     RECT  50.88 21.541 51.432 25.139 ;
     RECT  34.272 25.091 35.352 25.187 ;
     RECT  59.1 24.899 60.216 25.189 ;
     RECT  20.352 25.045 22.296 25.283 ;
     RECT  26.7 24.469 27.384 25.475 ;
     RECT  34.272 25.187 35.112 25.475 ;
     RECT  51 25.139 51.432 25.475 ;
     RECT  55.584 24.563 57.624 25.475 ;
     RECT  55.584 25.475 56.856 25.571 ;
     RECT  44.208 24.805 45.912 25.667 ;
     RECT  30.816 24.997 30.84 25.715 ;
     RECT  44.208 25.667 44.328 25.715 ;
     RECT  58.992 25.189 60.216 25.715 ;
     RECT  21.3 25.283 22.296 25.763 ;
     RECT  37.5 24.325 37.944 25.763 ;
     RECT  56.4 25.571 56.856 25.763 ;
     RECT  58.992 25.715 59.412 25.859 ;
     RECT  39.36 25.045 40.512 25.955 ;
     RECT  44.208 25.715 44.232 25.955 ;
     RECT  23.616 23.987 25.368 26.003 ;
     RECT  29.088 24.611 29.712 26.339 ;
     RECT  34.368 25.475 35.112 26.483 ;
     RECT  15.9 23.845 18.912 26.533 ;
     RECT  56.4 25.763 56.808 27.203 ;
     RECT  2.4 2.151 2.712 27.819 ;
     RECT  5.1 2.151 5.412 27.819 ;
     RECT  7.8 2.151 8.112 27.819 ;
     RECT  10.5 2.151 10.812 27.819 ;
     RECT  13.2 2.151 13.512 27.819 ;
     RECT  15.9 26.533 19.464 27.819 ;
     RECT  21.3 25.763 21.612 27.819 ;
     RECT  24 26.003 25.368 27.819 ;
     RECT  26.7 25.475 27.012 27.819 ;
     RECT  29.4 26.339 29.712 27.819 ;
     RECT  32.1 22.259 32.412 27.819 ;
     RECT  34.8 26.483 35.112 27.819 ;
     RECT  37.5 25.763 37.812 27.819 ;
     RECT  40.2 25.955 40.512 27.819 ;
     RECT  42.9 25.139 43.212 27.819 ;
     RECT  45.6 25.667 45.912 27.819 ;
     RECT  48.3 24.611 48.612 27.819 ;
     RECT  51 25.475 51.312 27.819 ;
     RECT  53.7 21.875 54.012 27.819 ;
     RECT  56.4 27.203 56.712 27.819 ;
     RECT  59.1 25.859 59.412 27.819 ;
     RECT  61.8 17.699 62.112 27.819 ;
     RECT  2.592 27.819 2.712 27.833 ;
     RECT  5.292 27.819 5.412 27.833 ;
     RECT  7.992 27.819 8.112 27.833 ;
     RECT  10.692 27.819 10.812 27.833 ;
     RECT  13.392 27.819 13.512 27.833 ;
     RECT  16.092 27.819 19.464 27.833 ;
     RECT  21.492 27.819 21.612 27.833 ;
     RECT  24.192 27.819 25.368 27.833 ;
     RECT  26.892 27.819 27.012 27.833 ;
     RECT  29.592 27.819 29.712 27.833 ;
     RECT  32.292 27.819 32.412 27.833 ;
     RECT  34.992 27.819 35.112 27.833 ;
     RECT  37.692 27.819 37.812 27.833 ;
     RECT  40.392 27.819 40.512 27.833 ;
     RECT  43.092 27.819 43.212 27.833 ;
     RECT  45.792 27.819 45.912 27.833 ;
     RECT  48.492 27.819 48.612 27.833 ;
     RECT  51.192 27.819 51.312 27.833 ;
     RECT  53.892 27.819 54.012 27.833 ;
     RECT  56.592 27.819 56.712 27.833 ;
     RECT  59.292 27.819 59.412 27.833 ;
     RECT  61.992 27.819 62.112 27.833 ;
     RECT  24.816 27.833 25.368 30.083 ;
     RECT  16.464 27.833 19.464 30.132 ;
     RECT  16.488 30.132 16.56 30.16 ;
     RECT  16.584 30.132 16.656 30.16 ;
     RECT  16.68 30.132 16.752 30.16 ;
     RECT  16.776 30.132 16.848 30.16 ;
     RECT  16.872 30.132 16.944 30.16 ;
     RECT  16.968 30.132 17.04 30.16 ;
     RECT  17.064 30.132 17.136 30.16 ;
     RECT  17.16 30.132 17.232 30.16 ;
     RECT  17.256 30.132 17.328 30.16 ;
     RECT  17.352 30.132 17.424 30.16 ;
     RECT  17.448 30.132 17.52 30.16 ;
     RECT  17.544 30.132 17.616 30.16 ;
     RECT  17.64 30.132 17.712 30.16 ;
     RECT  17.736 30.132 17.808 30.16 ;
     RECT  17.832 30.132 17.904 30.16 ;
     RECT  17.928 30.132 18 30.16 ;
     RECT  18.024 30.132 18.096 30.16 ;
     RECT  18.12 30.132 18.192 30.16 ;
     RECT  18.216 30.132 18.288 30.16 ;
     RECT  18.312 30.132 18.384 30.16 ;
     RECT  18.408 30.132 18.48 30.16 ;
     RECT  18.504 30.132 18.576 30.16 ;
     RECT  18.6 30.132 18.672 30.16 ;
     RECT  18.696 30.132 18.768 30.16 ;
     RECT  18.792 30.132 18.864 30.16 ;
     RECT  18.888 30.132 18.96 30.16 ;
     RECT  18.984 30.132 19.056 30.16 ;
     RECT  19.08 30.132 19.152 30.16 ;
     RECT  19.176 30.132 19.248 30.16 ;
     RECT  19.272 30.132 19.344 30.16 ;
     RECT  19.368 30.132 19.44 30.16 ;
     RECT  24.816 30.083 25.272 30.179 ;
     RECT  48.612 2.821 49.968 4.115 ;
     RECT  49.992 2.821 51 4.115 ;
     RECT  46.776 3.397 48.3 5.219 ;
     RECT  43.212 4.501 44.352 5.171 ;
     RECT  44.376 4.501 45.6 5.171 ;
     RECT  52.488 4.501 53.7 4.693 ;
     RECT  51.432 4.547 52.464 5.171 ;
     RECT  52.488 4.693 53.568 5.029 ;
     RECT  40.512 4.837 41.568 6.275 ;
     RECT  41.592 4.837 42.9 6.037 ;
     RECT  52.536 5.029 53.568 5.747 ;
     RECT  43.212 5.171 45.6 5.941 ;
     RECT  51.432 5.171 52.512 5.747 ;
     RECT  46.008 5.219 48.3 6.229 ;
     RECT  56.712 5.605 58.128 6.371 ;
     RECT  53.184 5.747 53.568 7.093 ;
     RECT  43.212 5.941 45.12 6.229 ;
     RECT  41.592 6.037 42.768 6.275 ;
     RECT  43.212 6.229 44.688 12.517 ;
     RECT  46.008 6.229 47.52 6.899 ;
     RECT  40.512 6.275 42.768 6.613 ;
     RECT  51.312 6.323 51.432 7.381 ;
     RECT  56.712 6.371 57.336 6.805 ;
     RECT  41.496 6.613 42.768 7.139 ;
     RECT  37.812 6.805 38.976 7.715 ;
     RECT  60.36 6.805 61.8 8.195 ;
     RECT  45.912 6.899 47.52 7.381 ;
     RECT  54.552 7.093 55.632 8.435 ;
     RECT  40.512 7.139 42.768 7.475 ;
     RECT  23.904 7.187 24 8.245 ;
     RECT  53.184 7.283 53.568 7.381 ;
     RECT  45.912 7.381 47.424 8.147 ;
     RECT  51.912 7.381 53.568 8.485 ;
     RECT  40.512 7.475 42.9 7.765 ;
     RECT  37.812 7.715 39.312 9.155 ;
     RECT  40.512 7.765 41.808 9.299 ;
     RECT  41.832 7.765 42.9 9.299 ;
     RECT  48.612 8.051 48.744 9.013 ;
     RECT  30.84 8.149 32.1 9.683 ;
     RECT  22.488 8.245 24 12.949 ;
     RECT  54.552 8.435 55.824 10.019 ;
     RECT  36.072 8.437 37.056 8.485 ;
     RECT  52.488 8.485 53.568 9.205 ;
     RECT  48.612 9.013 49.728 9.779 ;
     RECT  49.752 9.013 51 9.779 ;
     RECT  51.312 9.251 52.464 11.219 ;
     RECT  40.512 9.299 42.9 10.213 ;
     RECT  32.412 9.349 33.936 9.925 ;
     RECT  16.584 9.493 18 13.139 ;
     RECT  30.312 9.683 32.1 11.029 ;
     RECT  32.412 9.925 33.648 10.835 ;
     RECT  54.552 10.019 56.4 11.173 ;
     RECT  41.016 10.213 42.9 10.741 ;
     RECT  45.912 10.213 47.088 10.883 ;
     RECT  41.544 10.741 42.9 11.365 ;
     RECT  32.412 10.835 33.936 13.669 ;
     RECT  29.28 10.883 29.4 11.893 ;
     RECT  40.512 10.883 41.52 12.323 ;
     RECT  45.912 10.883 47.568 11.701 ;
     RECT  52.488 10.979 53.568 11.219 ;
     RECT  30.84 11.029 32.1 11.987 ;
     RECT  54.936 11.173 56.4 13.907 ;
     RECT  41.832 11.365 42.9 12.227 ;
     RECT  46.296 11.701 47.568 13.139 ;
     RECT  25.272 11.749 26.7 11.941 ;
     RECT  56.712 11.987 56.904 12.325 ;
     RECT  53.568 12.035 53.7 13.477 ;
     RECT  41.544 12.227 42.9 12.323 ;
     RECT  42.768 12.323 42.9 12.469 ;
     RECT  56.712 12.325 57.84 15.589 ;
     RECT  57.864 12.325 59.1 19.525 ;
     RECT  38.328 12.517 39.792 13.667 ;
     RECT  43.212 12.517 44.496 15.491 ;
     RECT  25.608 12.755 26.7 15.875 ;
     RECT  22.776 12.949 24 12.997 ;
     RECT  48.792 13.333 50.16 13.859 ;
     RECT  44.52 13.379 45.6 15.491 ;
     RECT  52.296 13.477 53.7 14.339 ;
     RECT  21.612 13.667 22.752 15.493 ;
     RECT  32.412 13.669 33.888 15.301 ;
     RECT  35.112 13.715 36.144 14.725 ;
     RECT  18.912 14.197 20.016 14.389 ;
     RECT  36.168 14.675 37.5 16.405 ;
     RECT  20.04 14.867 21.3 17.123 ;
     RECT  46.152 15.013 47.568 16.019 ;
     RECT  19.032 15.299 20.016 16.933 ;
     RECT  22.872 15.443 24 17.123 ;
     RECT  28.752 15.443 29.4 16.501 ;
     RECT  25.56 15.875 26.7 19.235 ;
     RECT  29.712 16.019 29.832 17.461 ;
     RECT  32.52 16.019 33.888 16.595 ;
     RECT  32.412 16.595 33.888 18.851 ;
     RECT  51.312 17.029 52.656 18.851 ;
     RECT  52.68 17.029 53.7 18.851 ;
     RECT  56.712 17.075 57.84 18.421 ;
     RECT  21.912 17.123 24 17.605 ;
     RECT  36.168 17.267 37.5 18.757 ;
     RECT  21.912 17.605 23.04 17.651 ;
     RECT  21.612 17.651 23.04 23.987 ;
     RECT  54.36 17.893 55.728 18.755 ;
     RECT  29.712 18.275 30.216 19.765 ;
     RECT  56.712 18.421 57.744 21.155 ;
     RECT  43.212 18.565 44.352 20.003 ;
     RECT  44.376 18.565 45.6 20.003 ;
     RECT  45.912 18.803 46.152 20.293 ;
     RECT  34.08 18.851 34.8 19.909 ;
     RECT  54.012 18.851 54.12 19.861 ;
     RECT  25.368 19.235 26.7 27.819 ;
     RECT  49.416 19.237 50.88 20.291 ;
     RECT  57.96 19.525 59.1 21.683 ;
     RECT  43.212 20.003 45.6 20.101 ;
     RECT  43.212 20.101 44.448 21.637 ;
     RECT  45.912 20.293 46.944 21.155 ;
     RECT  46.968 20.293 48.3 21.155 ;
     RECT  54.12 21.109 55.44 21.875 ;
     RECT  36.024 21.155 37.5 25.091 ;
     RECT  56.712 21.155 57.936 21.683 ;
     RECT  30.408 21.541 31.872 21.683 ;
     RECT  40.512 21.541 41.904 22.451 ;
     RECT  41.928 21.541 42.9 22.451 ;
     RECT  43.212 21.637 44.304 24.805 ;
     RECT  56.712 21.683 59.1 22.741 ;
     RECT  54.012 21.875 55.44 24.563 ;
     RECT  49.896 22.021 50.88 22.163 ;
     RECT  42.48 22.451 42.9 23.845 ;
     RECT  37.812 22.741 38.976 23.269 ;
     RECT  39 22.741 40.2 23.315 ;
     RECT  56.712 22.741 58.992 23.029 ;
     RECT  56.856 23.029 58.992 23.077 ;
     RECT  57.624 23.077 58.992 23.605 ;
     RECT  37.812 23.269 38.784 24.035 ;
     RECT  38.808 23.315 40.2 24.035 ;
     RECT  57.624 23.605 58.656 24.131 ;
     RECT  16.968 23.701 18.384 23.845 ;
     RECT  21.612 23.987 23.616 25.045 ;
     RECT  37.812 24.035 40.2 24.325 ;
     RECT  57.624 24.131 59.1 25.189 ;
     RECT  18.912 24.229 20.352 25.283 ;
     RECT  37.944 24.325 40.2 25.045 ;
     RECT  43.212 24.805 44.208 25.955 ;
     RECT  29.712 24.997 30.816 25.715 ;
     RECT  30.84 24.997 32.1 25.715 ;
     RECT  22.296 25.045 23.616 25.763 ;
     RECT  37.944 25.045 39.36 25.763 ;
     RECT  57.624 25.189 58.992 25.475 ;
     RECT  18.912 25.283 19.464 26.533 ;
     RECT  44.328 25.667 45.6 25.715 ;
     RECT  44.232 25.715 45.6 25.955 ;
     RECT  25.368 27.819 26.892 27.833 ;
  END
END qfd_landh0_128_NE_65x30
END LIBRARY
